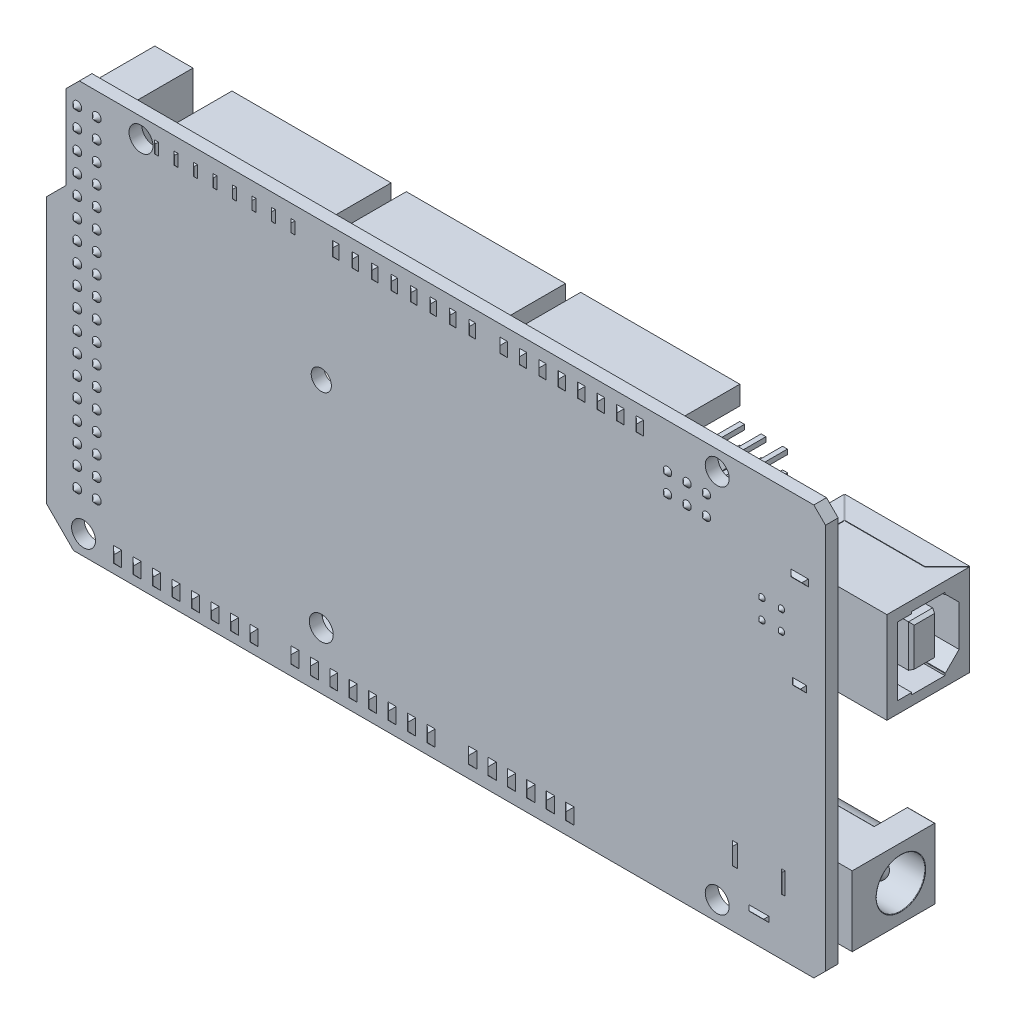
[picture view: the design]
SolidWorks part; units mm, degrees
ref_plane "Front Plane" through (0, 0, 0) normal (0, 0, 1) x (1, 0, 0)
ref_plane "Top Plane" through (0, 0, 0) normal (0, 1, 0) x (1, 0, 0)
ref_plane "Right Plane" through (0, 0, 0) normal (1, 0, 0) x (0, 0, -1)
sketch "Sketch1" plane through (0, 0, 0) normal (0, 0, 1) x (1, 0, 0)
  line L1 (-50.8, 26.7081) -> (50.8, 26.7081)
  line L2 (-50.8, 26.7081) -> (-50.8, -26.7081)
  line L3 (-50.8, -26.7081) -> (50.8, -26.7081)
  line L4 (50.8, 26.7081) -> (50.8, -26.7081)
  line L5 (-50.8, 26.7081) -> (50.8, -26.7081) construction
  line L6 (-50.8, -26.7081) -> (50.8, 26.7081) construction
  point P0 (0, 0)
  dimension "D1" = 101.6
  dimension "D2" = 53.4162
extrude "Boss-Extrude1" add sketch "Sketch1" along normal blind 1.651
sketch "Sketch2" plane through (0, 0, 0) normal (0, 0, -1) x (-1, 0, 0)
  line L0 (50.8, -26.7081) -> (-50.8, -26.7081) construction
  line L1 (41.7576, 25.4889) -> (46.736, 25.4889)
  line L2 (41.7576, 25.4889) -> (41.7576, -20.7899)
  line L3 (41.7576, -20.7899) -> (46.736, -20.7899)
  line L4 (46.736, 25.4889) -> (46.736, -20.7899)
  line L5 (41.7576, 25.4889) -> (46.736, -20.7899) construction
  line L6 (41.7576, -20.7899) -> (46.736, 25.4889) construction
  line L7 (50.8, 26.7081) -> (50.8, -26.7081) construction
  line L8 (-50.8, 26.7081) -> (50.8, 26.7081) construction
  line L9 (36.6776, 25.4381) -> (15.9258, 25.4381)
  line L10 (36.6776, 25.4381) -> (36.6776, 22.9743)
  line L11 (36.6776, 22.9743) -> (15.9258, 22.9743)
  line L12 (15.9258, 25.4381) -> (15.9258, 22.9743)
  line L13 (36.6776, 25.4381) -> (15.9258, 22.9743) construction
  line L14 (36.6776, 22.9743) -> (15.9258, 25.4381) construction
  line L15 (-6.8072, 25.4381) -> (-6.8072, 22.9743)
  line L16 (13.9446, 25.4381) -> (-6.8072, 25.4381)
  line L17 (13.9446, 22.9743) -> (-6.8072, 22.9743)
  line L18 (13.9446, 25.4381) -> (13.9446, 22.9743)
  line L19 (-29.5402, 25.4381) -> (-29.5402, 22.9743)
  line L20 (-8.7884, 25.4381) -> (-29.5402, 25.4381)
  line L21 (-8.7884, 22.9743) -> (-29.5402, 22.9743)
  line L22 (-8.7884, 25.4381) -> (-8.7884, 22.9743)
  line L23 (15.9258, 25.4381) -> (-6.8072, 25.4381) construction
  line L24 (-1.016, -22.8981) -> (-1.016, -25.3619)
  line L25 (42.545, -22.8981) -> (21.717, -22.8981)
  line L26 (42.545, -22.8981) -> (42.545, -25.3619)
  line L27 (42.545, -25.3619) -> (21.717, -25.3619)
  line L28 (21.717, -22.8981) -> (21.717, -25.3619)
  line L29 (42.545, -22.8981) -> (21.717, -25.3619) construction
  line L30 (42.545, -25.3619) -> (21.717, -22.8981) construction
  line L31 (19.812, -22.8981) -> (19.812, -25.3619)
  line L32 (19.812, -22.8981) -> (-1.016, -22.8981)
  line L33 (19.812, -25.3619) -> (-1.016, -25.3619)
  line L35 (-3.175, -22.9125) -> (-18.8722, -22.9125)
  line L36 (-3.175, -22.9125) -> (-3.175, -25.3619)
  line L37 (-3.175, -25.3619) -> (-18.8722, -25.3619)
  line L38 (-18.8722, -22.9125) -> (-18.8722, -25.3619)
  point P0 (44.2468, 2.3495)
  point P9 (26.3017, 24.2062)
  point P16 (32.131, -24.13)
  dimension "D1" = 4.9784
  dimension "D2" = 46.2788
  dimension "D3" = 5.9182
  dimension "D4" = 4.064
  dimension "D5" = 20.7518
  dimension "D6" = 2.4638
  dimension "D7" = 1.27
  dimension "D8" = 5.08
  dimension "D10" = 22.733
  dimension "D11" = 2.4638
  dimension "D12" = 20.828
  dimension "D13" = 8.255
  dimension "D14" = 1.3462
  dimension "D15" = 15.6972
  dimension "D16" = 2
  dimension "D17" = 2.159
  dimension "D18" = 13.7922
  dimension "D9" = 3
extrude "Boss-Extrude2" add sketch "Sketch2" along normal blind 8.5598
sketch "Sketch3" plane through (0, 0, 0) normal (0, 0, -1) x (-1, 0, 0)
  line L0 (-50.8, -26.7081) -> (-50.8, 26.7081) construction
  line L1 (-57.15, 17.4371) -> (-40.8432, 17.4371)
  line L2 (-57.15, 17.4371) -> (-57.15, 5.4991)
  line L3 (-57.15, 5.4991) -> (-40.8432, 5.4991)
  line L4 (-40.8432, 17.4371) -> (-40.8432, 5.4991)
  line L5 (-57.15, 17.4371) -> (-40.8432, 5.4991) construction
  line L6 (-57.15, 5.4991) -> (-40.8432, 17.4371) construction
  line L7 (-50.8, 26.7081) -> (50.8, 26.7081) construction
  point P0 (-48.9966, 11.4681)
  dimension "D1" = 16.3068
  dimension "D2" = 11.938
  dimension "D3" = 6.35
  dimension "D4" = 9.271
extrude "Boss-Extrude3" add sketch "Sketch3" along normal blind 10.795
sketch "Sketch4" plane through (0, 0, 0) normal (0, 0, -1) x (-1, 0, 0)
  line L0 (-50.8, -26.7081) -> (-50.8, 5.4991) construction
  line L1 (-52.6288, -13.7541) -> (-38.4048, -13.7541)
  line L2 (-52.6288, -13.7541) -> (-52.6288, -22.8981)
  line L3 (-52.6288, -22.8981) -> (-38.4048, -22.8981)
  line L4 (-38.4048, -13.7541) -> (-38.4048, -22.8981)
  line L5 (-52.6288, -13.7541) -> (-38.4048, -22.8981) construction
  line L6 (-52.6288, -22.8981) -> (-38.4048, -13.7541) construction
  line L7 (50.8, -26.7081) -> (-50.8, -26.7081) construction
  point P0 (-45.5168, -18.3261)
  dimension "D1" = 9.144
  dimension "D2" = 14.224
  dimension "D3" = 1.8288
  dimension "D4" = 3.81
extrude "Boss-Extrude4" add sketch "Sketch4" along normal blind 6.477
sketch "Sketch5" plane through (0, 0, -6.477) normal (0, 0, -1) x (-1, 0, 0)
  line L0 (-52.6288, -22.8981) -> (-38.4048, -22.8981) construction
  line L1 (-52.6288, -13.7541) -> (-49.0728, -13.7541)
  line L2 (-52.6288, -13.7541) -> (-52.6288, -22.8981)
  line L3 (-52.6288, -22.8981) -> (-49.0728, -22.8981)
  line L4 (-49.0728, -13.7541) -> (-49.0728, -22.8981)
  dimension "D1" = 3.556
extrude "Boss-Extrude5" add sketch "Sketch5" along normal blind 4.318
sketch "Sketch6" plane through (49.0728, 0, 0) normal (-1, 0, 0) x (0, 0, 1)
  line L0 (-6.477, -22.8981) -> (-6.477, -13.7541) construction
  line L1 (-6.477, -14.5161) -> (-6.477, -22.1361)
  arc A0 (-6.477, -14.5161) -> (-6.477, -22.1361) centre (-6.477, -18.3261) ccw
  dimension "D1" = 7.62
extrude "Boss-Extrude6" add sketch "Sketch6" along normal up to surface (10.668 mm away)
sketch "Sketch7" plane through (0, 0, -6.477) normal (0, 0, -1) x (-1, 0, 0)
  line L0 (-38.4048, -14.5161) -> (-49.0728, -14.5161) construction
  line L1 (-38.4048, -13.7541) -> (-40.005, -13.7541)
  line L2 (-38.4048, -13.7541) -> (-38.4048, -14.5161)
  line L3 (-38.4048, -14.5161) -> (-40.005, -14.5161)
  line L4 (-40.005, -13.7541) -> (-40.005, -14.5161)
  line L5 (-49.0728, -22.8981) -> (-38.4048, -22.8981) construction
  line L6 (-38.4048, -22.1361) -> (-40.005, -22.1361)
  line L7 (-38.4048, -22.1361) -> (-38.4048, -22.8981)
  line L8 (-38.4048, -22.8981) -> (-40.005, -22.8981)
  line L9 (-40.005, -22.1361) -> (-40.005, -22.8981)
  dimension "D1" = 1.6002
  dimension "D2" = 1.6002
extrude "Cut-Extrude1" cut sketch "Sketch7" against normal up to surface (6.477 mm away)
sketch "Sketch8" plane through (52.6288, 0, 0) normal (1, 0, 0) x (0, 0, -1)
  line L0 (10.795, -18.3261) -> (0, -18.3261) construction
  line L1 (10.795, -13.7541) -> (10.795, -22.8981) construction
  line L2 (0, -13.7541) -> (0, -22.8981) construction
  circle A0 centre (6.35, -18.3261) radius 3.175
  dimension "D1" = 0
  dimension "D2" = 6.35
  dimension "D3" = 4.445
extrude "Cut-Extrude2" cut sketch "Sketch8" against normal blind 12.065
sketch "Sketch9" plane through (40.5638, 0, 0) normal (1, 0, 0) x (0, 0, -1)
  circle A0 centre (6.35, -18.3261) radius 1.016
  dimension "D1" = 2.032
extrude "Boss-Extrude7" add sketch "Sketch9" along normal blind 10.16
fillet "Fillet1" radius 1.016 1 edges at (50.7238, -17.3101, -6.35)
sketch "Sketch10" plane through (57.15, 0, 0) normal (1, 0, 0) x (0, 0, -1)
  line L0 (10.795, 17.4371) -> (0, 5.4991) construction
  line L1 (10.795, 5.4991) -> (0, 17.4371) construction
  line L2 (10.795, 5.4991) -> (0, 5.4991) construction
  line L3 (7.6389, 15.9131) -> (7.5565, 15.9131)
  line L4 (9.4169, 14.1351) -> (9.4169, 8.8011)
  line L5 (7.6389, 7.0231) -> (7.5565, 7.0231)
  line L6 (1.3781, 15.9131) -> (1.3781, 7.0231)
  line L7 (9.4169, 15.9131) -> (1.3781, 7.0231) construction
  line L8 (9.4169, 7.0231) -> (1.3781, 15.9131) construction
  line L9 (9.4169, 11.4681) -> (1.3781, 11.4681) construction
  line L10 (3.2385, 7.0231) -> (1.3781, 7.0231)
  line L11 (7.5565, 7.0231) -> (7.5565, 6.7691)
  line L12 (7.5565, 6.7691) -> (3.2385, 6.7691)
  line L13 (3.2385, 7.0231) -> (3.2385, 6.7691)
  line L14 (7.5565, 7.2771) -> (3.2385, 6.7691) construction
  line L15 (7.5565, 6.7691) -> (3.2385, 7.2771) construction
  line L16 (3.2385, 15.9131) -> (3.2385, 16.1671)
  line L17 (7.5565, 16.1671) -> (3.2385, 16.1671)
  line L18 (7.5565, 15.9131) -> (7.5565, 16.1671)
  line L19 (3.2385, 15.9131) -> (1.3781, 15.9131)
  line L20 (9.4169, 8.8011) -> (7.6389, 7.0231)
  line L21 (9.4169, 14.1351) -> (7.6389, 15.9131)
  point P8 (5.3975, 11.4681)
  point P15 (5.3975, 7.0231)
  dimension "D1" = 1.524
  dimension "D2" = 0.508
  dimension "D3" = 4.318
  dimension "D4" = 1.778
  dimension "D5" = 1.778
  dimension "D6" = 45
  dimension "D7" = 45
extrude "Cut-Extrude3" cut sketch "Sketch10" against normal blind 13.97
sketch "Sketch11" plane through (43.18, 0, 0) normal (1, 0, 0) x (0, 0, -1)
  line L0 (10.795, 17.4371) -> (0, 5.4991) construction
  line L1 (10.795, 5.4991) -> (0, 17.4371) construction
  line L3 (6.9723, 14.2113) -> (3.8227, 14.2113)
  line L4 (6.9723, 14.2113) -> (6.9723, 8.7249)
  line L5 (6.9723, 8.7249) -> (3.8227, 8.7249)
  line L6 (3.8227, 14.2113) -> (3.8227, 8.7249)
  line L7 (6.9723, 14.2113) -> (3.8227, 8.7249) construction
  line L8 (6.9723, 8.7249) -> (3.8227, 14.2113) construction
  point P8 (5.3975, 11.4681)
  dimension "D1" = 3.1496
  dimension "D2" = 5.4864
extrude "Boss-Extrude8" add sketch "Sketch11" along normal blind 13.462
chamfer "Chamfer1" distance 0.254 angle 63 4 edges at (56.642, 14.2113, -5.3975) (56.642, 11.4681, -6.9723) (56.642, 8.7249, -5.3975) (56.642, 11.4681, -3.8227)
ref_plane "Plane1" through (0, 11.4681, 0) normal (0, 1, 0) x (-1, 0, 0)
sketch "Sketch12" plane through (0, 17.4371, 0) normal (0, 1, 0) x (1, 0, 0)
  line L1 (43.7896, 10.795) -> (57.15, 10.795)
  line L2 (40.8432, 10.7315) -> (43.7896, 7.7851)
  line L3 (43.8531, 7.8486) -> (54.2036, 7.8486)
  line L4 (40.8432, 0) -> (43.7896, 0)
  line L5 (40.9067, 10.795) -> (43.8531, 7.8486)
  line L6 (57.15, 10.795) -> (54.2036, 7.8486)
  line L7 (40.8432, 0) -> (40.8432, 10.7315)
  line L8 (40.9067, 10.795) -> (43.7896, 10.795)
  line L9 (43.7896, 0) -> (43.7896, 7.7851)
  dimension "D1" = 2.9464
  dimension "D2" = 45
  dimension "D3" = 2.9464
  dimension "D4" = 45
  dimension "D5" = 0.0635
  dimension "D6" = 45
extrude "Boss-Extrude9" add sketch "Sketch12" along normal blind 0.0635
mirror "Mirror1" about plane through (0, 11.4681, 0) normal (0, 1, 0) of "Boss-Extrude9"
chamfer "Chamfer2" distance 1.524 angle 45 2 edges at (50.8, -26.7081, 0.8255) (50.8, 26.7081, 0.8255)
chamfer "Chamfer3" distance 3.556 angle 45 1 edges at (-50.8, -26.7081, 0.8255)
sketch "Sketch13" plane through (0, 0, 0) normal (0, 0, -1) x (-1, 0, 0)
  line L1 (50.8, 26.7081) -> (50.8, -23.1521) construction
  line L2 (-49.276, 26.7081) -> (50.8, 26.7081) construction
  line L3 (48.26, 24.9447) -> (48.26, 14.0081)
  line L4 (50.8, 11.4681) -> (48.26, 14.0081)
  line L5 (48.26, 24.9447) -> (46.4966, 26.7081)
  line L6 (46.4966, 26.7081) -> (50.8, 26.7081)
  line L7 (50.8, 26.7081) -> (50.8, 11.4681)
  dimension "D1" = 15.24
  dimension "D2" = 2.54
  dimension "D3" = 45
extrude "Cut-Extrude4" cut sketch "Sketch13" against normal up to next
sketch "Sketch14" plane through (0, 0, 0) normal (0, 0, -1) x (-1, 0, 0)
  line L1 (-6.9605, 8.5631) -> (7.073, 8.5631)
  line L2 (-6.9605, 8.5631) -> (-6.9605, -5.6349)
  line L3 (-6.9605, -5.6349) -> (7.073, -5.6349)
  line L4 (7.073, 8.5631) -> (7.073, -5.6349)
  line L5 (-24.3309, -1.1659) -> (-21.5659, -1.1659)
  line L6 (-24.3309, -1.1659) -> (-24.3309, -2.574)
  line L7 (-24.3309, -2.574) -> (-21.5659, -2.574)
  line L8 (-21.5659, -1.1659) -> (-21.5659, -2.574)
  line L9 (-33.5092, 10.32) -> (-28.4497, 10.32)
  line L10 (-33.5092, 10.32) -> (-33.5092, 5.3949)
  line L11 (-33.5092, 5.3949) -> (-28.4497, 5.3949)
  line L12 (-28.4497, 10.32) -> (-28.4497, 5.3949)
  line L13 (-43.9403, -6.0414) -> (-40.6713, -6.0414)
  line L14 (-43.9403, -6.0414) -> (-43.9403, -12.5341)
  line L15 (-43.9403, -12.5341) -> (-40.6713, -12.5341)
  line L16 (-40.6713, -6.0414) -> (-40.6713, -12.5341)
  line L17 (-31.173, -23.0456) -> (-27.138, -23.0456)
  line L18 (-31.173, -23.0456) -> (-31.173, -25.4924)
  line L19 (-31.173, -25.4924) -> (-27.138, -25.4924)
  line L20 (-27.138, -23.0456) -> (-27.138, -25.4924)
  line L21 (-33.7999, -4.2562) -> (-30.9794, -4.2562)
  line L22 (-33.7999, -4.2562) -> (-33.7999, -7.1173)
  line L23 (-33.7999, -7.1173) -> (-30.9794, -7.1173)
  line L24 (-30.9794, -4.2562) -> (-30.9794, -7.1173)
  line L25 (-32.8056, -8.9233) -> (-31.8519, -8.9233)
  line L26 (-32.8056, -8.9233) -> (-32.8056, -12.1294)
  line L27 (-32.8056, -12.1294) -> (-31.8519, -12.1294)
  line L28 (-31.8519, -8.9233) -> (-31.8519, -12.1294)
  line L29 (-30.0459, -9.4914) -> (-28.4497, -9.4914)
  line L30 (-30.0459, -9.4914) -> (-30.0459, -10.2219)
  line L31 (-30.0459, -10.2219) -> (-28.4497, -10.2219)
  line L32 (-28.4497, -9.4914) -> (-28.4497, -10.2219)
  line L33 (-36.7827, -8.6595) -> (-35.9914, -8.6595)
  line L34 (-36.7827, -8.6595) -> (-36.7827, -10.2219)
  line L35 (-36.7827, -10.2219) -> (-35.9914, -10.2219)
  line L36 (-35.9914, -8.6595) -> (-35.9914, -10.2219)
  line L37 (-48.1172, 1.9462) -> (-44.9541, 1.9462)
  line L38 (-48.1172, 1.9462) -> (-48.1172, -2.574)
  line L39 (-48.1172, -2.574) -> (-44.9541, -2.574)
  line L40 (-44.9541, 1.9462) -> (-44.9541, -2.574)
  line L41 (-42.3058, 0.1921) -> (-41.1584, 0.1921)
  line L42 (-42.3058, 0.1921) -> (-42.3058, -2.574)
  line L43 (-42.3058, -2.574) -> (-41.1584, -2.574)
  line L44 (-41.1584, 0.1921) -> (-41.1584, -2.574)
  line L45 (-12.8797, -19.5259) -> (-11.332, -19.5259)
  line L46 (-12.8797, -19.5259) -> (-12.8797, -20.252)
  line L47 (-12.8797, -20.252) -> (-11.332, -20.252)
  line L48 (-11.332, -19.5259) -> (-11.332, -20.252)
  line L49 (-17.7394, -11.1441) -> (-16.7743, -11.1441)
  line L50 (-17.7394, -11.1441) -> (-17.7394, -13.2747)
  line L51 (-17.7394, -13.2747) -> (-16.7743, -13.2747)
  line L52 (-16.7743, -11.1441) -> (-16.7743, -13.2747)
  line L53 (-10.7102, -11.6175) -> (-9.7086, -11.6175)
  line L54 (-10.7102, -11.6175) -> (-10.7102, -13.0744)
  line L55 (-10.7102, -13.0744) -> (-9.7086, -13.0744)
  line L56 (-9.7086, -11.6175) -> (-9.7086, -13.0744)
  line L57 (-13.0047, -10.7617) -> (-11.73, -10.7617)
  line L58 (-13.0047, -10.7617) -> (-13.0047, -14.0213)
  line L59 (-13.0047, -14.0213) -> (-11.73, -14.0213)
  line L60 (-11.73, -10.7617) -> (-11.73, -14.0213)
  line L61 (-16.091, -10.7617) -> (-14.2392, -10.7617)
  line L62 (-16.091, -10.7617) -> (-16.091, -14.0213)
  line L63 (-16.091, -14.0213) -> (-14.2392, -14.0213)
  line L64 (-14.2392, -10.7617) -> (-14.2392, -14.0213)
  line L65 (-23.6628, -8.3755) -> (-22.1074, -8.3755)
  line L66 (-23.6628, -8.3755) -> (-23.6628, -9.1237)
  line L67 (-23.6628, -9.1237) -> (-22.1074, -9.1237)
  line L68 (-22.1074, -8.3755) -> (-22.1074, -9.1237)
  line L69 (-23.5707, -5.0699) -> (-22.0069, -5.0699)
  line L70 (-23.5707, -5.0699) -> (-23.5707, -5.8311)
  line L71 (-23.5707, -5.8311) -> (-22.0069, -5.8311)
  line L72 (-22.0069, -5.0699) -> (-22.0069, -5.8311)
  line L73 (-39.6477, 4.309) -> (-38.0454, 4.309)
  line L74 (-39.6477, 4.309) -> (-39.6477, 3.6337)
  line L75 (-39.6477, 3.6337) -> (-38.0454, 3.6337)
  line L76 (-38.0454, 4.309) -> (-38.0454, 3.6337)
  line L77 (-39.5152, 2.6802) -> (-38.0454, 2.6802)
  line L78 (-39.5152, 2.6802) -> (-39.5152, 1.9462)
  line L79 (-39.5152, 1.9462) -> (-38.0454, 1.9462)
  line L80 (-38.0454, 2.6802) -> (-38.0454, 1.9462)
  line L81 (-36.3871, 2.6802) -> (-34.854, 2.6802)
  line L82 (-36.3871, 2.6802) -> (-36.3871, 1.9462)
  line L83 (-36.3871, 1.9462) -> (-34.854, 1.9462)
  line L84 (-34.854, 2.6802) -> (-34.854, 1.9462)
  line L85 (-33.1723, 2.8127) -> (-31.5965, 2.8127)
  line L86 (-33.1723, 2.8127) -> (-33.1723, 1.9462)
  line L87 (-33.1723, 1.9462) -> (-31.5965, 1.9462)
  line L88 (-31.5965, 2.8127) -> (-31.5965, 1.9462)
  line L89 (-30.0459, 2.8127) -> (-28.5657, 2.8127)
  line L90 (-30.0459, 2.8127) -> (-30.0459, 1.9462)
  line L91 (-30.0459, 1.9462) -> (-28.5657, 1.9462)
  line L92 (-28.5657, 2.8127) -> (-28.5657, 1.9462)
  line L93 (-26.941, 2.8127) -> (-25.3776, 2.8127)
  line L94 (-26.941, 2.8127) -> (-26.941, 1.9462)
  line L95 (-26.941, 1.9462) -> (-25.3776, 1.9462)
  line L96 (-25.3776, 2.8127) -> (-25.3776, 1.9462)
  line L97 (-23.3697, 5.7605) -> (-22.3121, 5.7605)
  line L98 (-23.3697, 5.7605) -> (-23.3697, 2.5417)
  line L99 (-23.3697, 2.5417) -> (-22.3121, 2.5417)
  line L100 (-22.3121, 5.7605) -> (-22.3121, 2.5417)
  line L101 (-23.8854, 8.0069) -> (-22.1074, 8.0069)
  line L102 (-23.8854, 8.0069) -> (-23.8854, 6.7341)
  line L103 (-23.8854, 6.7341) -> (-22.1074, 6.7341)
  line L104 (-22.1074, 8.0069) -> (-22.1074, 6.7341)
  line L105 (-23.8854, 10.32) -> (-22.1074, 10.32)
  line L106 (-23.8854, 10.32) -> (-23.8854, 9.0606)
  line L107 (-23.8854, 9.0606) -> (-22.1074, 9.0606)
  line L108 (-22.1074, 10.32) -> (-22.1074, 9.0606)
  line L109 (-23.3697, 14.0967) -> (-22.5161, 14.0967)
  line L110 (-23.3697, 14.0967) -> (-23.3697, 10.8407)
  line L111 (-23.3697, 10.8407) -> (-22.5161, 10.8407)
  line L112 (-22.5161, 14.0967) -> (-22.5161, 10.8407)
  line L113 (-23.8854, 15.886) -> (-22.1074, 15.886)
  line L114 (-23.8854, 15.886) -> (-23.8854, 14.654)
  line L115 (-23.8854, 14.654) -> (-22.1074, 14.654)
  line L116 (-22.1074, 15.886) -> (-22.1074, 14.654)
  line L117 (-23.7484, 17.9417) -> (-22.3121, 17.9417)
  line L118 (-23.7484, 17.9417) -> (-23.7484, 17.187)
  line L119 (-23.7484, 17.187) -> (-22.3121, 17.187)
  line L120 (-22.3121, 17.9417) -> (-22.3121, 17.187)
  line L121 (-43.674, 18.8311) -> (-41.7321, 18.8311)
  line L122 (-43.674, 18.8311) -> (-43.674, 17.7416)
  line L123 (-43.674, 17.7416) -> (-41.7321, 17.7416)
  line L124 (-41.7321, 18.8311) -> (-41.7321, 17.7416)
  line L125 (-39.6477, 15.6816) -> (-38.0454, 15.6816)
  line L126 (-39.6477, 15.6816) -> (-39.6477, 14.9091)
  line L127 (-39.6477, 14.9091) -> (-38.0454, 14.9091)
  line L128 (-38.0454, 15.6816) -> (-38.0454, 14.9091)
  line L129 (-39.6477, 13.3641) -> (-38.0454, 13.3641)
  line L130 (-39.6477, 13.3641) -> (-39.6477, 12.4687)
  line L131 (-39.6477, 12.4687) -> (-38.0454, 12.4687)
  line L132 (-38.0454, 13.3641) -> (-38.0454, 12.4687)
  line L133 (-39.3497, 11.7365) -> (-38.3867, 11.7365)
  line L134 (-39.3497, 11.7365) -> (-39.3497, 8.5631)
  line L135 (-39.3497, 8.5631) -> (-38.3867, 8.5631)
  line L136 (-38.3867, 11.7365) -> (-38.3867, 8.5631)
  line L137 (-39.6477, 7.8575) -> (-38.0454, 7.8575)
  line L138 (-39.6477, 7.8575) -> (-39.6477, 6.9215)
  line L139 (-39.6477, 6.9215) -> (-38.0454, 6.9215)
  line L140 (-38.0454, 7.8575) -> (-38.0454, 6.9215)
  line L141 (24.8756, 10.8407) -> (26.6802, 10.8407)
  line L142 (24.8756, 10.8407) -> (24.8756, 9.4206)
  line L143 (24.8756, 9.4206) -> (26.6802, 9.4206)
  line L144 (26.6802, 10.8407) -> (26.6802, 9.4206)
  line L145 (29.6259, 11.7365) -> (30.8732, 11.7365)
  line L146 (29.6259, 11.7365) -> (29.6259, 8.3325)
  line L147 (29.6259, 8.3325) -> (30.8732, 8.3325)
  line L148 (30.8732, 11.7365) -> (30.8732, 8.3325)
  line L149 (-38.9776, 20.9935) -> (-37.1574, 20.9935)
  line L150 (-38.9776, 20.9935) -> (-38.9776, 17.7416)
  line L151 (-38.9776, 17.7416) -> (-37.1574, 17.7416)
  line L152 (-37.1574, 20.9935) -> (-37.1574, 17.7416)
extrude "Boss-Extrude10" add sketch "Sketch14" along normal blind 1.397
sketch "Sketch15" plane through (0, 0, 0) normal (0, 0, -1) x (-1, 0, 0)
  line L1 (20.5142, 4.069) -> (26.9751, 4.069)
  line L2 (20.5142, 4.069) -> (20.5142, -2.21)
  line L3 (20.5142, -2.21) -> (26.9751, -2.21)
  line L4 (26.9751, 4.069) -> (26.9751, -2.21)
extrude "Boss-Extrude11" add sketch "Sketch15" along normal blind 2.286
sketch "Sketch16" plane through (0, 0, -2.286) normal (0, 0, -1) x (-1, 0, 0)
  line L0 (20.5142, 4.069) -> (26.9751, -2.21) construction
  circle A0 centre (23.7447, 0.9295) radius 1.524
  dimension "D1" = 3.048
extrude "Boss-Extrude12" add sketch "Sketch16" along normal blind 1.016
sketch "Sketch17" plane through (0, 0, 0) normal (0, 0, -1) x (-1, 0, 0)
  line L0 (-32.3335, 0.8451) -> (-32.3335, -2.9138) construction
  line L1 (-36.2828, -2.9138) -> (-28.3841, -2.9138)
  line L2 (-36.2828, -2.9138) -> (-36.2828, 0.8451) construction
  line L3 (-36.2828, 0.8451) -> (-28.3841, 0.8451)
  line L4 (-28.3841, -2.9138) -> (-28.3841, 0.8451) construction
  arc A0 (-36.2828, -2.9138) -> (-36.2828, 0.8451) centre (-35.9606, -1.0343) cw
  arc A1 (-28.3841, -2.9138) -> (-28.3841, 0.8451) centre (-28.7063, -1.0343) ccw
extrude "Boss-Extrude13" add sketch "Sketch17" along normal blind 3.3528
fillet "Fillet2" radius 0.508 4 edges at (32.3335, 0.8451, -3.3528) (26.7995, -1.0343, -3.3528) (32.3335, -2.9138, -3.3528) (37.8675, -1.0343, -3.3528)
sketch "Sketch19" plane through (0, 0, 0) normal (0, 0, -1) x (-1, 0, 0)
  circle A0 centre (-32.7701, -18.1074) radius 3.302
  circle A1 centre (-25.5812, -18.1074) radius 3.302
  dimension "D1" = 6.604
extrude "Boss-Extrude14" add sketch "Sketch19" along normal blind 5.461
fillet "Fillet3" radius 0.254 2 edges at (22.2792, -18.1074, -5.461) (29.4681, -18.1074, -5.461)
sketch "Sketch20" plane through (0, 0, 0) normal (0, 0, -1) x (-1, 0, 0)
  line L0 (11.7084, 3.2926) -> (12.7244, 2.2766)
  line L1 (16.103, 4.9732) -> (17.119, 3.9572)
  line L2 (11.7084, 3.9572) -> (11.7084, 3.2926)
  line L3 (12.7244, 2.2766) -> (16.103, 2.2766)
  line L4 (17.119, 3.9572) -> (17.119, 3.2926)
  line L5 (16.103, 2.2766) -> (17.119, 3.2926)
  line L6 (12.7244, 4.9732) -> (16.103, 4.9732)
  line L7 (12.7244, 2.1792) -> (16.103, 2.1792)
  line L8 (12.7244, -0.5174) -> (16.103, -0.5174)
  line L9 (11.7084, 3.9572) -> (12.7244, 4.9732)
  line L10 (11.7084, 0.4986) -> (12.7244, -0.5174)
  line L11 (11.7084, 1.1632) -> (11.7084, 0.4986)
  line L12 (11.7084, 1.1632) -> (12.7244, 2.1792)
  line L13 (16.103, 2.1792) -> (17.119, 1.1632)
  line L14 (17.119, 1.1632) -> (17.119, 0.4986)
  line L15 (16.103, -0.5174) -> (17.119, 0.4986)
  line L16 (12.7244, -0.6148) -> (16.103, -0.6148)
  line L17 (-36.5713, 21.0509) -> (-35.5553, 22.0669)
  line L18 (-35.5553, 22.0669) -> (-34.8949, 22.0669)
  line L19 (-36.5713, 21.0509) -> (-36.5713, 17.6727)
  line L20 (-35.5553, 16.6567) -> (-34.8949, 16.6567)
  line L21 (-33.8789, 21.0509) -> (-33.8789, 17.6727)
  line L22 (12.7244, -3.3114) -> (16.103, -3.3114)
  line L23 (11.7084, -2.2954) -> (12.7244, -3.3114)
  line L24 (11.7084, -1.6308) -> (11.7084, -2.2954)
  line L25 (11.7084, -1.6308) -> (12.7244, -0.6148)
  line L26 (16.103, -0.6148) -> (17.119, -1.6308)
  line L27 (17.119, -1.6308) -> (17.119, -2.2954)
  line L28 (16.103, -3.3114) -> (17.119, -2.2954)
  line L29 (12.7244, 4.9732) -> (12.7244, 2.1792) construction
  line L30 (-34.8949, 22.0669) -> (-33.8789, 21.0509)
  line L31 (-34.8949, 16.6567) -> (-33.8789, 17.6727)
  line L32 (-36.5713, 17.6727) -> (-35.5553, 16.6567)
  line L33 (-32.7613, 22.0669) -> (-32.1009, 22.0669)
  line L34 (-32.1009, 22.0669) -> (-31.0849, 21.0509)
  line L35 (-31.0849, 21.0509) -> (-31.0849, 17.6727)
  line L36 (-32.1009, 16.6567) -> (-31.0849, 17.6727)
  line L37 (-32.7613, 16.6567) -> (-32.1009, 16.6567)
  line L38 (-33.7773, 17.6727) -> (-32.7613, 16.6567)
  line L39 (-33.7773, 21.0509) -> (-33.7773, 17.6727)
  line L40 (-33.7773, 21.0509) -> (-32.7613, 22.0669)
  line L41 (-29.9673, 22.0669) -> (-29.3069, 22.0669)
  line L42 (-29.3069, 22.0669) -> (-28.2909, 21.0509)
  line L43 (-28.2909, 21.0509) -> (-28.2909, 17.6727)
  line L44 (-29.3069, 16.6567) -> (-28.2909, 17.6727)
  line L45 (-29.9673, 16.6567) -> (-29.3069, 16.6567)
  line L46 (-30.9833, 17.6727) -> (-29.9673, 16.6567)
  line L47 (-30.9833, 21.0509) -> (-30.9833, 17.6727)
  line L48 (-30.9833, 21.0509) -> (-29.9673, 22.0669)
  line L49 (-35.5553, 22.0669) -> (-32.7613, 22.0669) construction
  point P0 (11.7084, 4.9732)
  point P1 (17.119, -2.9495)
  point P2 (11.7084, -2.9495)
  point P3 (17.119, 4.9732)
  point P5 (17.119, 2.2766)
  point P6 (11.7084, 2.2766)
  point P14 (-36.5713, 22.0669)
  point P33 (-33.8789, 16.6567)
  point P34 (-36.5713, 16.6567)
  point P35 (-33.8789, 22.0669)
  dimension "D1" = 3
  dimension "D2" = 2.794
  dimension "D3" = 2.6965
  dimension "D8" = 41.029
  dimension "D4" = 5.4102
  dimension "D5" = 2.6924
  dimension "D6" = 5.4106
  dimension "D7" = 2.794
extrude "Boss-Extrude15" add sketch "Sketch20" along normal blind 2.54
sketch "Sketch21" plane through (0, 0, -2.54) normal (0, 0, -1) x (-1, 0, 0)
  line L0 (11.7084, 3.6249) -> (17.119, 3.6249) construction
  line L1 (11.7084, 3.9572) -> (11.7084, 3.2926) construction
  line L2 (17.119, 3.2926) -> (17.119, 3.9572) construction
  line L3 (14.4137, 4.9732) -> (14.4137, -3.3114) construction
  line L4 (16.103, 4.9732) -> (12.7244, 4.9732) construction
  line L5 (12.7244, -3.3114) -> (16.103, -3.3114) construction
  line L6 (12.7627, 1.1484) -> (13.3977, 1.1484)
  line L7 (12.7627, 3.9424) -> (13.3977, 3.9424)
  line L8 (12.7627, 3.9424) -> (12.7627, 3.3074)
  line L9 (12.7627, 3.3074) -> (13.3977, 3.3074)
  line L10 (13.3977, 3.9424) -> (13.3977, 3.3074)
  line L11 (12.7627, 3.9424) -> (13.3977, 3.3074) construction
  line L12 (12.7627, 3.3074) -> (13.3977, 3.9424) construction
  line L13 (12.7627, 1.1484) -> (12.7627, 0.5134)
  line L14 (13.3977, 1.1484) -> (13.3977, 0.5134)
  line L15 (12.7627, 0.5134) -> (13.3977, 0.5134)
  line L16 (12.7627, -1.6456) -> (13.3977, -1.6456)
  line L17 (12.7627, -1.6456) -> (12.7627, -2.2806)
  line L18 (13.3977, -1.6456) -> (13.3977, -2.2806)
  line L19 (12.7627, -2.2806) -> (13.3977, -2.2806)
  line L20 (12.7627, 3.9424) -> (12.7627, 1.1484) construction
  line L21 (15.4297, -1.6456) -> (15.4297, -2.2806)
  line L22 (16.0647, -2.2806) -> (15.4297, -2.2806)
  line L23 (16.0647, -1.6456) -> (16.0647, -2.2806)
  line L24 (16.0647, -1.6456) -> (15.4297, -1.6456)
  line L25 (16.0647, 0.5134) -> (15.4297, 0.5134)
  line L26 (15.4297, 1.1484) -> (15.4297, 0.5134)
  line L27 (16.0647, 1.1484) -> (16.0647, 0.5134)
  line L28 (16.0647, 1.1484) -> (15.4297, 1.1484)
  line L29 (16.0647, 3.3074) -> (15.4297, 3.3074)
  line L30 (15.4297, 3.9424) -> (15.4297, 3.3074)
  line L31 (16.0647, 3.9424) -> (16.0647, 3.3074)
  line L32 (16.0647, 3.9424) -> (15.4297, 3.9424)
  line L33 (-36.5713, 19.3618) -> (-28.2909, 19.3618) construction
  line L34 (-36.5713, 21.0509) -> (-36.5713, 17.6727) construction
  line L35 (-28.2909, 17.6727) -> (-28.2909, 21.0509) construction
  line L36 (-35.2251, 22.0669) -> (-35.2251, 16.6567) construction
  line L37 (-34.8949, 22.0669) -> (-35.5553, 22.0669) construction
  line L38 (-35.5553, 16.6567) -> (-34.8949, 16.6567) construction
  line L39 (-32.7486, 18.3458) -> (-32.7486, 17.7108)
  line L40 (-35.5426, 18.3458) -> (-34.9076, 18.3458)
  line L41 (-35.5426, 18.3458) -> (-35.5426, 17.7108)
  line L42 (-35.5426, 17.7108) -> (-34.9076, 17.7108)
  line L43 (-34.9076, 18.3458) -> (-34.9076, 17.7108)
  line L44 (-35.5426, 18.3458) -> (-34.9076, 17.7108) construction
  line L45 (-35.5426, 17.7108) -> (-34.9076, 18.3458) construction
  line L46 (-32.7486, 18.3458) -> (-32.1136, 18.3458)
  line L47 (-32.1136, 18.3458) -> (-32.1136, 17.7108)
  line L48 (-32.7486, 17.7108) -> (-32.1136, 17.7108)
  line L49 (-29.9546, 18.3458) -> (-29.9546, 17.7108)
  line L50 (-29.9546, 18.3458) -> (-29.3196, 18.3458)
  line L51 (-29.3196, 18.3458) -> (-29.3196, 17.7108)
  line L52 (-29.9546, 17.7108) -> (-29.3196, 17.7108)
  line L53 (-35.5426, 18.3458) -> (-32.7486, 18.3458) construction
  line L54 (-29.9546, 21.0128) -> (-29.3196, 21.0128)
  line L55 (-29.3196, 20.3778) -> (-29.3196, 21.0128)
  line L56 (-29.9546, 20.3778) -> (-29.9546, 21.0128)
  line L57 (-29.9546, 20.3778) -> (-29.3196, 20.3778)
  line L58 (-32.7486, 21.0128) -> (-32.1136, 21.0128)
  line L59 (-32.1136, 20.3778) -> (-32.1136, 21.0128)
  line L60 (-32.7486, 20.3778) -> (-32.7486, 21.0128)
  line L61 (-32.7486, 20.3778) -> (-32.1136, 20.3778)
  line L62 (-35.5426, 21.0128) -> (-34.9076, 21.0128)
  line L63 (-34.9076, 20.3778) -> (-34.9076, 21.0128)
  line L64 (-35.5426, 20.3778) -> (-34.9076, 20.3778)
  line L65 (-35.5426, 20.3778) -> (-35.5426, 21.0128)
  point P12 (13.0802, 3.6249)
  point P51 (-35.2251, 18.0283)
  dimension "D1" = 0.635
  dimension "D2" = 0.635
  dimension "D4" = 2.794
  dimension "D5" = 1.016
  dimension "D6" = 1.016
  dimension "D7" = 0.635
  dimension "D8" = 0.635
  dimension "D9" = 2.794
  dimension "D3" = 3
  dimension "D10" = 3
extrude "Boss-Extrude16" add sketch "Sketch21" along normal blind 6.223
chamfer "Chamfer4" distance 0.127 angle 45 48 edges at (-12.7627, -1.9631, -8.763) (-13.0802, -1.6456, -8.763) (-13.3977, -1.9631, -8.763) (-13.0802, -2.2806, -8.763) (-12.7627, 0.8309, -8.763) (-13.0802, 1.1484, -8.763) (-13.3977, 0.8309, -8.763) (-13.0802, 0.5134, -8.763) (-13.0802, 3.3074, -8.763) (-12.7627, 3.6249, -8.763) (-13.0802, 3.9424, -8.763) (-13.3977, 3.6249, -8.763) (-15.7472, 3.3074, -8.763) (-15.4297, 3.6249, -8.763) (-15.7472, 3.9424, -8.763) (-16.0647, 3.6249, -8.763) (-15.7472, 0.5134, -8.763) (-15.4297, 0.8309, -8.763) (-15.7472, 1.1484, -8.763) (-16.0647, 0.8309, -8.763) (-16.0647, -1.9631, -8.763) (-15.7472, -2.2806, -8.763) (-15.4297, -1.9631, -8.763) (-15.7472, -1.6456, -8.763) (35.2251, 17.7108, -8.763) (35.5426, 18.0283, -8.763) (35.2251, 18.3458, -8.763) (34.9076, 18.0283, -8.763) (35.2251, 21.0128, -8.763) (34.9076, 20.6953, -8.763) (35.2251, 20.3778, -8.763) (35.5426, 20.6953, -8.763) (32.4311, 21.0128, -8.763) (32.1136, 20.6953, -8.763) (32.4311, 20.3778, -8.763) (32.7486, 20.6953, -8.763) (29.6371, 21.0128, -8.763) (29.3196, 20.6953, -8.763) (29.6371, 20.3778, -8.763) (29.9546, 20.6953, -8.763) (32.7486, 18.0283, -8.763) (32.4311, 18.3458, -8.763) (32.1136, 18.0283, -8.763) (32.4311, 17.7108, -8.763) (29.9546, 18.0283, -8.763) (29.6371, 18.3458, -8.763) (29.3196, 18.0283, -8.763) (29.6371, 17.7108, -8.763)
sketch "Sketch22" plane through (0, 0, 0) normal (0, 0, -1) x (-1, 0, 0)
  line L0 (-50.8, -25.1841) -> (-50.8, -22.8981) construction
  line L1 (47.244, -26.7081) -> (-49.276, -26.7081) construction
  line L2 (-36.6776, -24.1681) -> (-36.6776, 25.7302) construction
  line L3 (-49.276, 26.7081) -> (46.4966, 26.7081) construction
  line L4 (14.9479, -19.2896) -> (14.9479, 8.7266) construction
  line L5 (50.8, 11.4681) -> (50.8, -23.1521) construction
  circle A0 centre (38.4556, 24.1681) radius 1.5621
  circle A1 centre (14.9479, 8.7266) radius 1.3153
  circle A2 centre (14.9479, -19.2896) radius 1.5621
  circle A3 centre (45.9486, -24.1681) radius 1.5621
  circle A4 centre (-36.6776, -24.1681) radius 1.5621
  circle A5 centre (-36.6776, 24.1681) radius 1.5621
  dimension "D1" = 3.1242
  dimension "D2" = 14.1224
  dimension "D3" = 2.54
  dimension "D4" = 2.54
  dimension "D5" = 82.6262
  dimension "D6" = 2.54
  dimension "D7" = 2.54
  dimension "D8" = 75.1332
  dimension "D9" = 28.0162
  dimension "D10" = 0
  dimension "D11" = 0
  dimension "D12" = 0
  dimension "D13" = 35.8521
extrude "Cut-Extrude5" cut sketch "Sketch22" against normal up to next
sketch "Sketch24" plane through (0, 0, -8.5598) normal (0, 0, -1) x (-1, 0, 0)
  line L0 (44.2468, 25.4889) -> (44.2468, -20.7899) construction
  line L1 (46.736, 25.4889) -> (41.7576, 25.4889) construction
  line L2 (41.7576, -20.7899) -> (46.736, -20.7899) construction
  line L3 (44.2468, 25.4889) -> (46.736, 25.4889) construction
  line L4 (41.7576, 2.3495) -> (46.736, 2.3495) construction
  line L5 (41.7576, 25.4889) -> (41.7576, -20.7899) construction
  line L6 (46.736, -20.7899) -> (46.736, 25.4889) construction
  line L7 (45.4914, 25.4889) -> (45.4914, 2.3495) construction
  line L8 (42.6402, 24.1681) -> (42.6402, 23.4442)
  line L9 (43.3641, 23.4442) -> (42.6402, 23.4442)
  line L10 (45.1294, 24.1681) -> (45.8533, 24.1681)
  line L11 (45.1294, 24.1681) -> (45.1294, 23.4442)
  line L12 (45.1294, 23.4442) -> (45.8533, 23.4442)
  line L13 (45.8533, 24.1681) -> (45.8533, 23.4442)
  line L14 (45.1294, 24.1681) -> (45.8533, 23.4442) construction
  line L15 (45.1294, 23.4442) -> (45.8533, 24.1681) construction
  line L16 (43.3641, 24.1681) -> (42.6402, 24.1681)
  line L17 (43.3641, 24.1681) -> (43.3641, 23.4442)
  line L18 (43.3642, 21.6281) -> (42.6403, 21.6281)
  line L19 (42.6403, 21.6281) -> (42.6403, 20.9042)
  line L20 (43.3642, 20.9042) -> (42.6403, 20.9042)
  line L21 (43.3642, 21.6281) -> (43.3642, 20.9042)
  line L22 (45.1295, 21.6281) -> (45.8534, 21.6281)
  line L23 (45.1295, 21.6281) -> (45.1295, 20.9042)
  line L24 (45.1295, 20.9042) -> (45.8534, 20.9042)
  line L25 (45.8534, 21.6281) -> (45.8534, 20.9042)
  line L26 (43.3642, 19.0881) -> (42.6403, 19.0881)
  line L27 (42.6403, 19.0881) -> (42.6403, 18.3642)
  line L28 (43.3642, 18.3642) -> (42.6403, 18.3642)
  line L29 (43.3642, 19.0881) -> (43.3642, 18.3642)
  line L30 (45.1295, 19.0881) -> (45.8534, 19.0881)
  line L31 (45.1295, 19.0881) -> (45.1295, 18.3642)
  line L32 (45.1295, 18.3642) -> (45.8534, 18.3642)
  line L33 (45.8534, 19.0881) -> (45.8534, 18.3642)
  line L34 (43.3642, 16.5481) -> (42.6403, 16.5481)
  line L35 (42.6403, 16.5481) -> (42.6403, 15.8242)
  line L36 (43.3642, 15.8242) -> (42.6403, 15.8242)
  line L37 (43.3642, 16.5481) -> (43.3642, 15.8242)
  line L38 (45.1295, 16.5481) -> (45.8534, 16.5481)
  line L39 (45.1295, 16.5481) -> (45.1295, 15.8242)
  line L40 (45.1295, 15.8242) -> (45.8534, 15.8242)
  line L41 (45.8534, 16.5481) -> (45.8534, 15.8242)
  line L42 (43.3642, 14.0081) -> (42.6403, 14.0081)
  line L43 (42.6403, 14.0081) -> (42.6403, 13.2842)
  line L44 (43.3642, 13.2842) -> (42.6403, 13.2842)
  line L45 (43.3642, 14.0081) -> (43.3642, 13.2842)
  line L46 (45.1295, 14.0081) -> (45.8534, 14.0081)
  line L47 (45.1295, 14.0081) -> (45.1295, 13.2842)
  line L48 (45.1295, 13.2842) -> (45.8534, 13.2842)
  line L49 (45.8534, 14.0081) -> (45.8534, 13.2842)
  line L50 (43.3642, 11.4681) -> (42.6403, 11.4681)
  line L51 (42.6403, 11.4681) -> (42.6403, 10.7442)
  line L52 (43.3642, 10.7442) -> (42.6403, 10.7442)
  line L53 (43.3642, 11.4681) -> (43.3642, 10.7442)
  line L54 (45.1295, 11.4681) -> (45.8534, 11.4681)
  line L55 (45.1295, 11.4681) -> (45.1295, 10.7442)
  line L56 (45.1295, 10.7442) -> (45.8534, 10.7442)
  line L57 (45.8534, 11.4681) -> (45.8534, 10.7442)
  line L58 (43.3642, 8.9281) -> (42.6403, 8.9281)
  line L59 (42.6403, 8.9281) -> (42.6403, 8.2042)
  line L60 (43.3642, 8.2042) -> (42.6403, 8.2042)
  line L61 (43.3642, 8.9281) -> (43.3642, 8.2042)
  line L62 (45.1295, 8.9281) -> (45.8534, 8.9281)
  line L63 (45.1295, 8.9281) -> (45.1295, 8.2042)
  line L64 (45.1295, 8.2042) -> (45.8534, 8.2042)
  line L65 (45.8534, 8.9281) -> (45.8534, 8.2042)
  line L66 (43.3642, 6.3881) -> (42.6403, 6.3881)
  line L67 (42.6403, 6.3881) -> (42.6403, 5.6642)
  line L68 (43.3642, 5.6642) -> (42.6403, 5.6642)
  line L69 (43.3642, 6.3881) -> (43.3642, 5.6642)
  line L70 (45.1295, 6.3881) -> (45.8534, 6.3881)
  line L71 (45.1295, 6.3881) -> (45.1295, 5.6642)
  line L72 (45.1295, 5.6642) -> (45.8534, 5.6642)
  line L73 (45.8534, 6.3881) -> (45.8534, 5.6642)
  line L74 (43.3642, 3.8481) -> (42.6403, 3.8481)
  line L75 (42.6403, 3.8481) -> (42.6403, 3.1242)
  line L76 (43.3642, 3.1242) -> (42.6403, 3.1242)
  line L77 (43.3642, 3.8481) -> (43.3642, 3.1242)
  line L78 (45.1295, 3.8481) -> (45.8534, 3.8481)
  line L79 (45.1295, 3.8481) -> (45.1295, 3.1242)
  line L80 (45.1295, 3.1242) -> (45.8534, 3.1242)
  line L81 (45.8534, 3.8481) -> (45.8534, 3.1242)
  line L82 (43.3642, 1.3081) -> (42.6403, 1.3081)
  line L83 (42.6403, 1.3081) -> (42.6403, 0.5842)
  line L84 (43.3642, 0.5842) -> (42.6403, 0.5842)
  line L85 (43.3642, 1.3081) -> (43.3642, 0.5842)
  line L86 (45.1295, 1.3081) -> (45.8534, 1.3081)
  line L87 (45.1295, 1.3081) -> (45.1295, 0.5842)
  line L88 (45.1295, 0.5842) -> (45.8534, 0.5842)
  line L89 (45.8534, 1.3081) -> (45.8534, 0.5842)
  line L90 (43.3642, -1.2319) -> (42.6403, -1.2319)
  line L91 (42.6403, -1.2319) -> (42.6403, -1.9558)
  line L92 (43.3642, -1.9558) -> (42.6403, -1.9558)
  line L93 (43.3642, -1.2319) -> (43.3642, -1.9558)
  line L94 (45.1295, -1.2319) -> (45.8534, -1.2319)
  line L95 (45.1295, -1.2319) -> (45.1295, -1.9558)
  line L96 (45.1295, -1.9558) -> (45.8534, -1.9558)
  line L97 (45.8534, -1.2319) -> (45.8534, -1.9558)
  line L98 (43.3642, -3.7719) -> (42.6403, -3.7719)
  line L99 (42.6403, -3.7719) -> (42.6403, -4.4958)
  line L100 (43.3642, -4.4958) -> (42.6403, -4.4958)
  line L101 (43.3642, -3.7719) -> (43.3642, -4.4958)
  line L102 (45.1295, -3.7719) -> (45.8534, -3.7719)
  line L103 (45.1295, -3.7719) -> (45.1295, -4.4958)
  line L104 (45.1295, -4.4958) -> (45.8534, -4.4958)
  line L105 (45.8534, -3.7719) -> (45.8534, -4.4958)
  line L106 (43.3642, -6.3119) -> (42.6403, -6.3119)
  line L107 (42.6403, -6.3119) -> (42.6403, -7.0358)
  line L108 (43.3642, -7.0358) -> (42.6403, -7.0358)
  line L109 (43.3642, -6.3119) -> (43.3642, -7.0358)
  line L110 (45.1295, -6.3119) -> (45.8534, -6.3119)
  line L111 (45.1295, -6.3119) -> (45.1295, -7.0358)
  line L112 (45.1295, -7.0358) -> (45.8534, -7.0358)
  line L113 (45.8534, -6.3119) -> (45.8534, -7.0358)
  line L114 (43.3642, -8.8519) -> (42.6403, -8.8519)
  line L115 (42.6403, -8.8519) -> (42.6403, -9.5758)
  line L116 (43.3642, -9.5758) -> (42.6403, -9.5758)
  line L117 (43.3642, -8.8519) -> (43.3642, -9.5758)
  line L118 (45.1295, -8.8519) -> (45.8534, -8.8519)
  line L119 (45.1295, -8.8519) -> (45.1295, -9.5758)
  line L120 (45.1295, -9.5758) -> (45.8534, -9.5758)
  line L121 (45.8534, -8.8519) -> (45.8534, -9.5758)
  line L122 (43.3642, -11.3919) -> (42.6403, -11.3919)
  line L123 (42.6403, -11.3919) -> (42.6403, -12.1158)
  line L124 (43.3642, -12.1158) -> (42.6403, -12.1158)
  line L125 (43.3642, -11.3919) -> (43.3642, -12.1158)
  line L126 (45.1295, -11.3919) -> (45.8534, -11.3919)
  line L127 (45.1295, -11.3919) -> (45.1295, -12.1158)
  line L128 (45.1295, -12.1158) -> (45.8534, -12.1158)
  line L129 (45.8534, -11.3919) -> (45.8534, -12.1158)
  line L130 (43.3642, -13.9319) -> (42.6403, -13.9319)
  line L131 (42.6403, -13.9319) -> (42.6403, -14.6558)
  line L132 (43.3642, -14.6558) -> (42.6403, -14.6558)
  line L133 (43.3642, -13.9319) -> (43.3642, -14.6558)
  line L134 (45.1295, -13.9319) -> (45.8534, -13.9319)
  line L135 (45.1295, -13.9319) -> (45.1295, -14.6558)
  line L136 (45.1295, -14.6558) -> (45.8534, -14.6558)
  line L137 (45.8534, -13.9319) -> (45.8534, -14.6558)
  line L138 (43.3642, -16.4719) -> (42.6403, -16.4719)
  line L139 (42.6403, -16.4719) -> (42.6403, -17.1958)
  line L140 (43.3642, -17.1958) -> (42.6403, -17.1958)
  line L141 (43.3642, -16.4719) -> (43.3642, -17.1958)
  line L142 (45.1295, -16.4719) -> (45.8534, -16.4719)
  line L143 (45.1295, -16.4719) -> (45.1295, -17.1958)
  line L144 (45.1295, -17.1958) -> (45.8534, -17.1958)
  line L145 (45.8534, -16.4719) -> (45.8534, -17.1958)
  line L146 (43.3642, -19.0119) -> (42.6403, -19.0119)
  line L147 (42.6403, -19.0119) -> (42.6403, -19.7358)
  line L148 (43.3642, -19.7358) -> (42.6403, -19.7358)
  line L149 (43.3642, -19.0119) -> (43.3642, -19.7358)
  line L150 (45.1295, -19.0119) -> (45.8534, -19.0119)
  line L151 (45.1295, -19.0119) -> (45.1295, -19.7358)
  line L152 (45.1295, -19.7358) -> (45.8534, -19.7358)
  line L153 (45.8534, -19.0119) -> (45.8534, -19.7358)
  line L154 (15.9258, 24.2062) -> (36.6776, 24.2062) construction
  line L155 (15.9258, 25.4381) -> (15.9258, 22.9743) construction
  line L156 (36.6776, 22.9743) -> (36.6776, 25.4381) construction
  line L157 (32.0929, 24.5682) -> (32.0929, 23.8443)
  line L158 (34.6329, 24.5682) -> (35.3568, 24.5682)
  line L159 (34.6329, 24.5682) -> (34.6329, 23.8443)
  line L160 (34.6329, 23.8443) -> (35.3568, 23.8443)
  line L161 (35.3568, 24.5682) -> (35.3568, 23.8443)
  line L162 (34.6329, 24.5682) -> (35.3568, 23.8443) construction
  line L163 (34.6329, 23.8443) -> (35.3568, 24.5682) construction
  line L164 (32.8168, 24.5682) -> (32.8168, 23.8443)
  line L165 (32.0929, 24.5682) -> (32.8168, 24.5682)
  line L166 (32.0929, 23.8443) -> (32.8168, 23.8443)
  line L167 (29.5529, 24.5682) -> (29.5529, 23.8443)
  line L168 (30.2768, 24.5682) -> (30.2768, 23.8443)
  line L169 (29.5529, 24.5682) -> (30.2768, 24.5682)
  line L170 (29.5529, 23.8443) -> (30.2768, 23.8443)
  line L171 (27.0129, 24.5682) -> (27.0129, 23.8443)
  line L172 (27.7368, 24.5682) -> (27.7368, 23.8443)
  line L173 (27.0129, 24.5682) -> (27.7368, 24.5682)
  line L174 (27.0129, 23.8443) -> (27.7368, 23.8443)
  line L175 (24.4729, 24.5682) -> (24.4729, 23.8443)
  line L176 (25.1968, 24.5682) -> (25.1968, 23.8443)
  line L177 (24.4729, 24.5682) -> (25.1968, 24.5682)
  line L178 (24.4729, 23.8443) -> (25.1968, 23.8443)
  line L179 (21.9329, 24.5681) -> (21.9329, 23.8442)
  line L180 (22.6568, 24.5681) -> (22.6568, 23.8442)
  line L181 (21.9329, 24.5681) -> (22.6568, 24.5681)
  line L182 (21.9329, 23.8442) -> (22.6568, 23.8442)
  line L183 (19.3929, 24.5681) -> (19.3929, 23.8442)
  line L184 (20.1168, 24.5681) -> (20.1168, 23.8442)
  line L185 (19.3929, 24.5681) -> (20.1168, 24.5681)
  line L186 (19.3929, 23.8442) -> (20.1168, 23.8442)
  line L187 (16.8529, 24.5681) -> (16.8529, 23.8442)
  line L188 (17.5768, 24.5681) -> (17.5768, 23.8442)
  line L189 (16.8529, 24.5681) -> (17.5768, 24.5681)
  line L190 (16.8529, 23.8442) -> (17.5768, 23.8442)
  line L191 (13.9446, 24.2062) -> (-6.8072, 24.2062) construction
  line L192 (13.9446, 22.9743) -> (13.9446, 25.4381) construction
  line L193 (-6.8072, 25.4381) -> (-6.8072, 22.9743) construction
  line L194 (9.3599, 24.5681) -> (10.0838, 24.5681)
  line L195 (11.8999, 24.5681) -> (12.6238, 24.5681)
  line L196 (11.8999, 24.5681) -> (11.8999, 23.8442)
  line L197 (11.8999, 23.8442) -> (12.6238, 23.8442)
  line L198 (12.6238, 24.5681) -> (12.6238, 23.8442)
  line L199 (11.8999, 24.5681) -> (12.6238, 23.8442) construction
  line L200 (11.8999, 23.8442) -> (12.6238, 24.5681) construction
  line L201 (9.3599, 24.5681) -> (9.3599, 23.8442)
  line L202 (9.3599, 23.8442) -> (10.0838, 23.8442)
  line L203 (10.0838, 24.5681) -> (10.0838, 23.8442)
  line L204 (6.8199, 24.5681) -> (7.5438, 24.5681)
  line L205 (6.8199, 24.5681) -> (6.8199, 23.8442)
  line L206 (6.8199, 23.8442) -> (7.5438, 23.8442)
  line L207 (7.5438, 24.5681) -> (7.5438, 23.8442)
  line L208 (4.2799, 24.5681) -> (5.0038, 24.5681)
  line L209 (4.2799, 24.5681) -> (4.2799, 23.8442)
  line L210 (4.2799, 23.8442) -> (5.0038, 23.8442)
  line L211 (5.0038, 24.5681) -> (5.0038, 23.8442)
  line L212 (1.7399, 24.5681) -> (2.4638, 24.5681)
  line L213 (1.7399, 24.5681) -> (1.7399, 23.8442)
  line L214 (1.7399, 23.8442) -> (2.4638, 23.8442)
  line L215 (2.4638, 24.5681) -> (2.4638, 23.8442)
  line L216 (-0.8001, 24.5681) -> (-0.0762, 24.5681)
  line L217 (-0.8001, 24.5681) -> (-0.8001, 23.8442)
  line L218 (-0.8001, 23.8442) -> (-0.0762, 23.8442)
  line L219 (-0.0762, 24.5681) -> (-0.0762, 23.8442)
  line L220 (-3.3401, 24.5681) -> (-2.6162, 24.5681)
  line L221 (-3.3401, 24.5681) -> (-3.3401, 23.8442)
  line L222 (-3.3401, 23.8442) -> (-2.6162, 23.8442)
  line L223 (-2.6162, 24.5681) -> (-2.6162, 23.8442)
  line L224 (-5.8801, 24.5681) -> (-5.1562, 24.5681)
  line L225 (-5.8801, 24.5681) -> (-5.8801, 23.8442)
  line L226 (-5.8801, 23.8442) -> (-5.1562, 23.8442)
  line L227 (-5.1562, 24.5681) -> (-5.1562, 23.8442)
  line L228 (-29.5402, 24.2062) -> (-8.7884, 24.2062) construction
  line L229 (-29.5402, 25.4381) -> (-29.5402, 22.9743) construction
  line L230 (-8.7884, 22.9743) -> (-8.7884, 25.4381) construction
  line L231 (-13.3731, 24.5681) -> (-12.6492, 24.5681)
  line L232 (-10.8331, 24.5681) -> (-10.1092, 24.5681)
  line L233 (-10.8331, 24.5681) -> (-10.8331, 23.8442)
  line L234 (-10.8331, 23.8442) -> (-10.1092, 23.8442)
  line L235 (-10.1092, 24.5681) -> (-10.1092, 23.8442)
  line L236 (-10.8331, 24.5681) -> (-10.1092, 23.8442) construction
  line L237 (-10.8331, 23.8442) -> (-10.1092, 24.5681) construction
  line L238 (-12.6492, 24.5681) -> (-12.6492, 23.8442)
  line L239 (-13.3731, 23.8442) -> (-12.6492, 23.8442)
  line L240 (-13.3731, 24.5681) -> (-13.3731, 23.8442)
  line L241 (-15.9131, 24.5681) -> (-15.1892, 24.5681)
  line L242 (-15.1892, 24.5681) -> (-15.1892, 23.8442)
  line L243 (-15.9131, 23.8442) -> (-15.1892, 23.8442)
  line L244 (-15.9131, 24.5681) -> (-15.9131, 23.8442)
  line L245 (-18.4531, 24.5681) -> (-17.7292, 24.5681)
  line L246 (-17.7292, 24.5681) -> (-17.7292, 23.8442)
  line L247 (-18.4531, 23.8442) -> (-17.7292, 23.8442)
  line L248 (-18.4531, 24.5681) -> (-18.4531, 23.8442)
  line L249 (-20.9931, 24.5681) -> (-20.2692, 24.5681)
  line L250 (-20.2692, 24.5681) -> (-20.2692, 23.8442)
  line L251 (-20.9931, 23.8442) -> (-20.2692, 23.8442)
  line L252 (-20.9931, 24.5681) -> (-20.9931, 23.8442)
  line L253 (-23.5331, 24.5681) -> (-22.8092, 24.5681)
  line L254 (-22.8092, 24.5681) -> (-22.8092, 23.8442)
  line L255 (-23.5331, 23.8442) -> (-22.8092, 23.8442)
  line L256 (-23.5331, 24.5681) -> (-23.5331, 23.8442)
  line L257 (-26.0731, 24.5681) -> (-25.3492, 24.5681)
  line L258 (-25.3492, 24.5681) -> (-25.3492, 23.8442)
  line L259 (-26.0731, 23.8442) -> (-25.3492, 23.8442)
  line L260 (-26.0731, 24.5681) -> (-26.0731, 23.8442)
  line L261 (-28.6131, 24.5681) -> (-27.8892, 24.5681)
  line L262 (-27.8892, 24.5681) -> (-27.8892, 23.8442)
  line L263 (-28.6131, 23.8442) -> (-27.8892, 23.8442)
  line L264 (-28.6131, 24.5681) -> (-28.6131, 23.8442)
  line L265 (42.545, -24.13) -> (21.717, -24.13) construction
  line L266 (42.545, -25.3619) -> (42.545, -22.8981) construction
  line L267 (21.717, -22.8981) -> (21.717, -25.3619) construction
  line L268 (42.545, -25.3619) -> (42.545, -22.8981) construction
  line L269 (40.5003, -23.7681) -> (41.2242, -23.7681)
  line L270 (40.5003, -23.7681) -> (40.5003, -24.492)
  line L271 (40.5003, -24.492) -> (41.2242, -24.492)
  line L272 (41.2242, -23.7681) -> (41.2242, -24.492)
  line L273 (40.5003, -23.7681) -> (41.2242, -24.492) construction
  line L274 (40.5003, -24.492) -> (41.2242, -23.7681) construction
  line L275 (37.9603, -23.7681) -> (38.6842, -23.7681)
  line L276 (37.9603, -23.7681) -> (37.9603, -24.492)
  line L277 (38.6842, -23.7681) -> (38.6842, -24.492)
  line L278 (37.9603, -24.492) -> (38.6842, -24.492)
  line L279 (35.4203, -23.7681) -> (36.1442, -23.7681)
  line L280 (35.4203, -23.7681) -> (35.4203, -24.492)
  line L281 (36.1442, -23.7681) -> (36.1442, -24.492)
  line L282 (35.4203, -24.492) -> (36.1442, -24.492)
  line L283 (32.8803, -23.7681) -> (33.6042, -23.7681)
  line L284 (32.8803, -23.7681) -> (32.8803, -24.492)
  line L285 (33.6042, -23.7681) -> (33.6042, -24.492)
  line L286 (32.8803, -24.492) -> (33.6042, -24.492)
  line L287 (30.3403, -23.7681) -> (31.0642, -23.7681)
  line L288 (30.3403, -23.7681) -> (30.3403, -24.492)
  line L289 (31.0642, -23.7681) -> (31.0642, -24.492)
  line L290 (30.3403, -24.492) -> (31.0642, -24.492)
  line L291 (27.8003, -23.7681) -> (28.5242, -23.7681)
  line L292 (27.8003, -23.7681) -> (27.8003, -24.492)
  line L293 (28.5242, -23.7681) -> (28.5242, -24.492)
  line L294 (27.8003, -24.492) -> (28.5242, -24.492)
  line L295 (25.2603, -23.7681) -> (25.9842, -23.7681)
  line L296 (25.2603, -23.7681) -> (25.2603, -24.492)
  line L297 (25.9842, -23.7681) -> (25.9842, -24.492)
  line L298 (25.2603, -24.492) -> (25.9842, -24.492)
  line L299 (22.7203, -23.7681) -> (23.4442, -23.7681)
  line L300 (22.7203, -23.7681) -> (22.7203, -24.492)
  line L301 (23.4442, -23.7681) -> (23.4442, -24.492)
  line L302 (22.7203, -24.492) -> (23.4442, -24.492)
  line L303 (-1.016, -24.13) -> (19.812, -24.13) construction
  line L304 (-1.016, -22.8981) -> (-1.016, -25.3619) construction
  line L305 (19.812, -25.3619) -> (19.812, -22.8981) construction
  line L306 (15.2273, -23.7681) -> (15.9512, -23.7681)
  line L307 (17.7673, -23.7681) -> (18.4912, -23.7681)
  line L308 (17.7673, -23.7681) -> (17.7673, -24.492)
  line L309 (17.7673, -24.492) -> (18.4912, -24.492)
  line L310 (18.4912, -23.7681) -> (18.4912, -24.492)
  line L311 (17.7673, -23.7681) -> (18.4912, -24.492) construction
  line L312 (17.7673, -24.492) -> (18.4912, -23.7681) construction
  line L313 (15.2273, -23.7681) -> (15.2273, -24.492)
  line L314 (15.9512, -23.7681) -> (15.9512, -24.492)
  line L315 (15.2273, -24.492) -> (15.9512, -24.492)
  line L316 (12.6873, -23.7681) -> (13.4112, -23.7681)
  line L317 (12.6873, -23.7681) -> (12.6873, -24.492)
  line L318 (13.4112, -23.7681) -> (13.4112, -24.492)
  line L319 (12.6873, -24.492) -> (13.4112, -24.492)
  line L320 (10.1473, -23.7681) -> (10.8712, -23.7681)
  line L321 (10.1473, -23.7681) -> (10.1473, -24.492)
  line L322 (10.8712, -23.7681) -> (10.8712, -24.492)
  line L323 (10.1473, -24.492) -> (10.8712, -24.492)
  line L324 (7.6073, -23.7681) -> (8.3312, -23.7681)
  line L325 (7.6073, -23.7681) -> (7.6073, -24.492)
  line L326 (8.3312, -23.7681) -> (8.3312, -24.492)
  line L327 (7.6073, -24.492) -> (8.3312, -24.492)
  line L328 (5.0673, -23.7681) -> (5.7912, -23.7681)
  line L329 (5.0673, -23.7681) -> (5.0673, -24.492)
  line L330 (5.7912, -23.7681) -> (5.7912, -24.492)
  line L331 (5.0673, -24.492) -> (5.7912, -24.492)
  line L332 (2.5273, -23.7681) -> (3.2512, -23.7681)
  line L333 (2.5273, -23.7681) -> (2.5273, -24.492)
  line L334 (3.2512, -23.7681) -> (3.2512, -24.492)
  line L335 (2.5273, -24.492) -> (3.2512, -24.492)
  line L336 (-0.0127, -23.7681) -> (0.7112, -23.7681)
  line L337 (-0.0127, -23.7681) -> (-0.0127, -24.492)
  line L338 (0.7112, -23.7681) -> (0.7112, -24.492)
  line L339 (-0.0127, -24.492) -> (0.7112, -24.492)
  line L340 (-18.8722, -24.1372) -> (-3.175, -24.1372) construction
  line L341 (-18.8722, -22.9125) -> (-18.8722, -25.3619) construction
  line L342 (-3.175, -25.3619) -> (-3.175, -22.9125) construction
  line L343 (-3.175, -25.3619) -> (-3.175, -22.9125) construction
  line L344 (-5.2197, -23.7752) -> (-4.4958, -23.7752)
  line L345 (-5.2197, -23.7752) -> (-5.2197, -24.4991)
  line L346 (-5.2197, -24.4991) -> (-4.4958, -24.4991)
  line L347 (-4.4958, -23.7752) -> (-4.4958, -24.4991)
  line L348 (-5.2197, -23.7752) -> (-4.4958, -24.4991) construction
  line L349 (-5.2197, -24.4991) -> (-4.4958, -23.7752) construction
  line L350 (-7.0358, -23.7752) -> (-7.0358, -24.4991)
  line L351 (-7.7597, -23.7752) -> (-7.0358, -23.7752)
  line L352 (-7.7597, -23.7752) -> (-7.7597, -24.4991)
  line L353 (-7.7597, -24.4991) -> (-7.0358, -24.4991)
  line L354 (-9.5758, -23.7752) -> (-9.5758, -24.4991)
  line L355 (-10.2997, -23.7752) -> (-9.5758, -23.7752)
  line L356 (-10.2997, -23.7752) -> (-10.2997, -24.4991)
  line L357 (-10.2997, -24.4991) -> (-9.5758, -24.4991)
  line L358 (-12.1158, -23.7752) -> (-12.1158, -24.4991)
  line L359 (-12.8397, -23.7752) -> (-12.1158, -23.7752)
  line L360 (-12.8397, -23.7752) -> (-12.8397, -24.4991)
  line L361 (-12.8397, -24.4991) -> (-12.1158, -24.4991)
  line L362 (-14.6558, -23.7752) -> (-14.6558, -24.4991)
  line L363 (-15.3797, -23.7752) -> (-14.6558, -23.7752)
  line L364 (-15.3797, -23.7752) -> (-15.3797, -24.4991)
  line L365 (-15.3797, -24.4991) -> (-14.6558, -24.4991)
  line L366 (-17.1958, -23.7752) -> (-17.1958, -24.4991)
  line L367 (-17.9197, -23.7752) -> (-17.1958, -23.7752)
  line L368 (-17.9197, -23.7752) -> (-17.9197, -24.4991)
  line L369 (-17.9197, -24.4991) -> (-17.1958, -24.4991)
  point P17 (45.4914, 23.8061)
  point P167 (34.9948, 24.2062)
  point P206 (12.2618, 24.2062)
  point P245 (-10.4712, 24.2062)
  point P284 (40.8623, -24.13)
  point P325 (18.1292, -24.13)
  point P364 (-4.8577, -24.1372)
  dimension "D1" = 0.7239
  dimension "D2" = 0.7239
  dimension "D3" = 1.3208
  dimension "D5" = 0.7239
  dimension "D6" = 0.7239
  dimension "D7" = 1.3208
  dimension "D8" = 0.7239
  dimension "D9" = 0.7239
  dimension "D10" = 1.3208
  dimension "D11" = 0.7239
  dimension "D12" = 1.3208
  dimension "D13" = 0.7239
  dimension "D14" = 0.7239
  dimension "D15" = 1.3208
  dimension "D16" = 0.7239
  dimension "D17" = 1.3208
  dimension "D18" = 0.7239
  dimension "D19" = 0.7239
  dimension "D20" = 1.3208
  dimension "D4" = 18
extrude "Cut-Extrude6" cut sketch "Sketch24" against normal blind 6.35
chamfer "Chamfer5" distance 0.127 angle 45 356 edges at (-26.3017, 25.4381, -8.5598) (-36.6776, 24.2062, -8.5598) (-26.3017, 22.9743, -8.5598) (-15.9258, 24.2062, -8.5598) (-34.6329, 24.2062, -8.5598) (-34.9948, 23.8443, -8.5598) (-35.3568, 24.2062, -8.5598) (-34.9948, 24.5682, -8.5598) (-32.4548, 24.5682, -8.5598) (-32.0929, 24.2062, -8.5598) (-32.4548, 23.8443, -8.5598) (-32.8168, 24.2062, -8.5598) (-29.9148, 24.5682, -8.5598) (-29.5529, 24.2062, -8.5598) (-29.9148, 23.8443, -8.5598) (-30.2768, 24.2062, -8.5598) (-27.3748, 24.5682, -8.5598) (-27.0129, 24.2062, -8.5598) (-27.3748, 23.8443, -8.5598) (-27.7368, 24.2062, -8.5598) (-24.8348, 24.5682, -8.5598) (-24.4729, 24.2062, -8.5598) (-24.8348, 23.8443, -8.5598) (-25.1968, 24.2062, -8.5598) (-22.2948, 24.5681, -8.5598) (-21.9329, 24.2062, -8.5598) (-22.2948, 23.8442, -8.5598) (-22.6568, 24.2062, -8.5598) (-19.7548, 24.5681, -8.5598) (-19.3929, 24.2062, -8.5598) (-19.7548, 23.8442, -8.5598) (-20.1168, 24.2062, -8.5598) (-17.2148, 24.5681, -8.5598) (-16.8529, 24.2062, -8.5598) (-17.2148, 23.8442, -8.5598) (-17.5768, 24.2062, -8.5598) (6.8072, 24.2062, -8.5598) (-3.5687, 25.4381, -8.5598) (-13.9446, 24.2062, -8.5598) (-3.5687, 22.9743, -8.5598) (-12.2618, 24.5681, -8.5598) (-11.8999, 24.2062, -8.5598) (-12.2618, 23.8442, -8.5598) (-12.6238, 24.2062, -8.5598) (-9.7218, 24.5681, -8.5598) (-9.3599, 24.2062, -8.5598) (-9.7218, 23.8442, -8.5598) (-10.0838, 24.2062, -8.5598) (-7.1818, 24.5681, -8.5598) (-6.8199, 24.2062, -8.5598) (-7.1818, 23.8442, -8.5598) (-7.5438, 24.2062, -8.5598) (-4.6418, 24.5681, -8.5598) (-4.2799, 24.2062, -8.5598) (-4.6418, 23.8442, -8.5598) (-5.0038, 24.2062, -8.5598) (-2.1018, 24.5681, -8.5598) (-1.7399, 24.2062, -8.5598) (-2.1018, 23.8442, -8.5598) (-2.4638, 24.2062, -8.5598) (0.4382, 24.5681, -8.5598) (0.8001, 24.2062, -8.5598) (0.4382, 23.8442, -8.5598) (0.0762, 24.2062, -8.5598) (2.9782, 24.5681, -8.5598) (3.3401, 24.2062, -8.5598) (2.9782, 23.8442, -8.5598) (2.6162, 24.2062, -8.5598) (5.5182, 24.5681, -8.5598) (5.8801, 24.2062, -8.5598) (5.5182, 23.8442, -8.5598) (5.1562, 24.2062, -8.5598) (29.5402, 24.2062, -8.5598) (19.1643, 25.4381, -8.5598) (8.7884, 24.2062, -8.5598) (19.1643, 22.9743, -8.5598) (10.4712, 24.5681, -8.5598) (10.8331, 24.2062, -8.5598) (10.4712, 23.8442, -8.5598) (10.1092, 24.2062, -8.5598) (12.6492, 24.2062, -8.5598) (13.0112, 24.5681, -8.5598) (13.3731, 24.2062, -8.5598) (13.0112, 23.8442, -8.5598) (15.1892, 24.2062, -8.5598) (15.5512, 24.5681, -8.5598) (15.9131, 24.2062, -8.5598) (15.5512, 23.8442, -8.5598) (17.7292, 24.2062, -8.5598) (18.0912, 24.5681, -8.5598) (18.4531, 24.2062, -8.5598) (18.0912, 23.8442, -8.5598) (20.2692, 24.2062, -8.5598) (20.6312, 24.5681, -8.5598) (20.9931, 24.2062, -8.5598) (20.6312, 23.8442, -8.5598) (22.8092, 24.2062, -8.5598) (23.1712, 24.5681, -8.5598) (23.5331, 24.2062, -8.5598) (23.1712, 23.8442, -8.5598) (25.3492, 24.2062, -8.5598) (25.7112, 24.5681, -8.5598) (26.0731, 24.2062, -8.5598) (25.7112, 23.8442, -8.5598) (27.8892, 24.2062, -8.5598) (28.2512, 24.5681, -8.5598) (28.6131, 24.2062, -8.5598) (28.2512, 23.8442, -8.5598) (-44.2468, -20.7899, -8.5598) (-41.7576, 2.3495, -8.5598) (-44.2468, 25.4889, -8.5598) (-46.736, 2.3495, -8.5598) (-42.6402, 23.8061, -8.5598) (-43.0022, 23.4442, -8.5598) (-43.3641, 23.8061, -8.5598) (-43.0022, 24.1681, -8.5598) (-45.4914, 24.1681, -8.5598) (-45.1294, 23.8061, -8.5598) (-45.4914, 23.4442, -8.5598) (-45.8533, 23.8061, -8.5598) (-43.0022, 20.9042, -8.5598) (-43.3642, 21.2661, -8.5598) (-43.0022, 21.6281, -8.5598) (-42.6403, 21.2661, -8.5598) (-45.4914, 21.6281, -8.5598) (-45.1295, 21.2661, -8.5598) (-45.4914, 20.9042, -8.5598) (-45.8534, 21.2661, -8.5598) (-43.0022, 18.3642, -8.5598) (-43.3642, 18.7261, -8.5598) (-43.0022, 19.0881, -8.5598) (-42.6403, 18.7261, -8.5598) (-45.4914, 19.0881, -8.5598) (-45.1295, 18.7261, -8.5598) (-45.4914, 18.3642, -8.5598) (-45.8534, 18.7261, -8.5598) (-43.0022, 15.8242, -8.5598) (-43.3642, 16.1861, -8.5598) (-43.0022, 16.5481, -8.5598) (-42.6403, 16.1861, -8.5598) (-45.4914, 16.5481, -8.5598) (-45.1295, 16.1861, -8.5598) (-45.4914, 15.8242, -8.5598) (-45.8534, 16.1861, -8.5598) (-43.0022, 13.2842, -8.5598) (-43.3642, 13.6461, -8.5598) (-43.0022, 14.0081, -8.5598) (-42.6403, 13.6461, -8.5598) (-45.4914, 14.0081, -8.5598) (-45.1295, 13.6461, -8.5598) (-45.4914, 13.2842, -8.5598) (-45.8534, 13.6461, -8.5598) (-43.0022, 10.7442, -8.5598) (-43.3642, 11.1061, -8.5598) (-43.0022, 11.4681, -8.5598) (-42.6403, 11.1061, -8.5598) (-45.4914, 11.4681, -8.5598) (-45.1295, 11.1061, -8.5598) (-45.4914, 10.7442, -8.5598) (-45.8534, 11.1061, -8.5598) (-43.0022, 8.2042, -8.5598) (-43.3642, 8.5661, -8.5598) (-43.0022, 8.9281, -8.5598) (-42.6403, 8.5661, -8.5598) (-45.4914, 8.9281, -8.5598) (-45.1295, 8.5661, -8.5598) (-45.4914, 8.2042, -8.5598) (-45.8534, 8.5661, -8.5598) (-43.0022, 5.6642, -8.5598) (-43.3642, 6.0261, -8.5598) (-43.0022, 6.3881, -8.5598) (-42.6403, 6.0261, -8.5598) (-45.4914, 6.3881, -8.5598) (-45.1295, 6.0261, -8.5598) (-45.4914, 5.6642, -8.5598) (-45.8534, 6.0261, -8.5598) (-43.0022, 3.1242, -8.5598) (-43.3642, 3.4861, -8.5598) (-43.0022, 3.8481, -8.5598) (-42.6403, 3.4861, -8.5598) (-45.4914, 3.8481, -8.5598) (-45.1295, 3.4861, -8.5598) (-45.4914, 3.1242, -8.5598) (-45.8534, 3.4861, -8.5598) (-43.0022, 0.5842, -8.5598) (-43.3642, 0.9461, -8.5598) (-43.0022, 1.3081, -8.5598) (-42.6403, 0.9461, -8.5598) (-45.4914, 1.3081, -8.5598) (-45.1295, 0.9461, -8.5598) (-45.4914, 0.5842, -8.5598) (-45.8534, 0.9461, -8.5598) (-43.0022, -1.9558, -8.5598) (-43.3642, -1.5939, -8.5598) (-43.0022, -1.2319, -8.5598) (-42.6403, -1.5939, -8.5598) (-45.4914, -1.2319, -8.5598) (-45.1295, -1.5939, -8.5598) (-45.4914, -1.9558, -8.5598) (-45.8534, -1.5939, -8.5598) (-43.0022, -4.4958, -8.5598) (-43.3642, -4.1339, -8.5598) (-43.0022, -3.7719, -8.5598) (-42.6403, -4.1339, -8.5598) (-45.4914, -3.7719, -8.5598) (-45.1295, -4.1339, -8.5598) (-45.4914, -4.4958, -8.5598) (-45.8534, -4.1339, -8.5598) (-43.0022, -7.0358, -8.5598) (-43.3642, -6.6739, -8.5598) (-43.0022, -6.3119, -8.5598) (-42.6403, -6.6739, -8.5598) (-45.4914, -6.3119, -8.5598) (-45.1295, -6.6739, -8.5598) (-45.4914, -7.0358, -8.5598) (-45.8534, -6.6739, -8.5598) (-43.0022, -9.5758, -8.5598) (-43.3642, -9.2139, -8.5598) (-43.0022, -8.8519, -8.5598) (-42.6403, -9.2139, -8.5598) (-45.4914, -8.8519, -8.5598) (-45.1295, -9.2139, -8.5598) (-45.4914, -9.5758, -8.5598) (-45.8534, -9.2139, -8.5598) (-43.0022, -12.1158, -8.5598) (-43.3642, -11.7539, -8.5598) (-43.0022, -11.3919, -8.5598) (-42.6403, -11.7539, -8.5598) (-45.4914, -11.3919, -8.5598) (-45.1295, -11.7539, -8.5598) (-45.4914, -12.1158, -8.5598) (-45.8534, -11.7539, -8.5598) (-43.0022, -14.6558, -8.5598) (-43.3642, -14.2939, -8.5598) (-43.0022, -13.9319, -8.5598) (-42.6403, -14.2939, -8.5598) (-45.4914, -13.9319, -8.5598) (-45.1295, -14.2939, -8.5598) (-45.4914, -14.6558, -8.5598) (-45.8534, -14.2939, -8.5598) (-43.0022, -17.1958, -8.5598) (-43.3642, -16.8339, -8.5598) (-43.0022, -16.4719, -8.5598) (-42.6403, -16.8339, -8.5598) (-45.4914, -16.4719, -8.5598) (-45.1295, -16.8339, -8.5598) (-45.4914, -17.1958, -8.5598) (-45.8534, -16.8339, -8.5598) (-43.0022, -19.7358, -8.5598) (-43.3642, -19.3739, -8.5598) (-43.0022, -19.0119, -8.5598) (-42.6403, -19.3739, -8.5598) (-45.4914, -19.0119, -8.5598) (-45.1295, -19.3739, -8.5598) (-45.4914, -19.7358, -8.5598) (-45.8534, -19.3739, -8.5598) (11.0236, -25.3619, -8.5598) (18.8722, -24.1372, -8.5598) (11.0236, -22.9125, -8.5598) (3.175, -24.1372, -8.5598) (5.2197, -24.1372, -8.5598) (4.8577, -24.4991, -8.5598) (4.4958, -24.1372, -8.5598) (4.8577, -23.7752, -8.5598) (7.3977, -23.7752, -8.5598) (7.7597, -24.1372, -8.5598) (7.3977, -24.4991, -8.5598) (7.0358, -24.1372, -8.5598) (9.9377, -23.7752, -8.5598) (10.2997, -24.1372, -8.5598) (9.9377, -24.4991, -8.5598) (9.5758, -24.1372, -8.5598) (12.4777, -23.7752, -8.5598) (12.8397, -24.1372, -8.5598) (12.4777, -24.4991, -8.5598) (12.1158, -24.1372, -8.5598) (15.0177, -23.7752, -8.5598) (15.3797, -24.1372, -8.5598) (15.0177, -24.4991, -8.5598) (14.6558, -24.1372, -8.5598) (17.5578, -23.7752, -8.5598) (17.9197, -24.1372, -8.5598) (17.5578, -24.4991, -8.5598) (17.1958, -24.1372, -8.5598) (1.016, -24.13, -8.5598) (-9.398, -22.8981, -8.5598) (-19.812, -24.13, -8.5598) (-9.398, -25.3619, -8.5598) (-18.1292, -23.7681, -8.5598) (-17.7673, -24.13, -8.5598) (-18.1292, -24.492, -8.5598) (-18.4912, -24.13, -8.5598) (-15.9512, -24.13, -8.5598) (-15.5892, -23.7681, -8.5598) (-15.2273, -24.13, -8.5598) (-15.5892, -24.492, -8.5598) (-13.4112, -24.13, -8.5598) (-13.0492, -23.7681, -8.5598) (-12.6873, -24.13, -8.5598) (-13.0492, -24.492, -8.5598) (-10.8712, -24.13, -8.5598) (-10.5092, -23.7681, -8.5598) (-10.1473, -24.13, -8.5598) (-10.5092, -24.492, -8.5598) (-8.3312, -24.13, -8.5598) (-7.9692, -23.7681, -8.5598) (-7.6073, -24.13, -8.5598) (-7.9692, -24.492, -8.5598) (-5.7912, -24.13, -8.5598) (-5.4292, -23.7681, -8.5598) (-5.0673, -24.13, -8.5598) (-5.4292, -24.492, -8.5598) (-3.2512, -24.13, -8.5598) (-2.8892, -23.7681, -8.5598) (-2.5273, -24.13, -8.5598) (-2.8892, -24.492, -8.5598) (-0.7112, -24.13, -8.5598) (-0.3492, -23.7681, -8.5598) (0.0127, -24.13, -8.5598) (-0.3492, -24.492, -8.5598) (-32.131, -22.8981, -8.5598) (-42.545, -24.13, -8.5598) (-32.131, -25.3619, -8.5598) (-21.717, -24.13, -8.5598) (-40.5003, -24.13, -8.5598) (-40.8623, -24.492, -8.5598) (-41.2242, -24.13, -8.5598) (-40.8623, -23.7681, -8.5598) (-38.3223, -23.7681, -8.5598) (-37.9603, -24.13, -8.5598) (-38.3223, -24.492, -8.5598) (-38.6842, -24.13, -8.5598) (-35.7823, -23.7681, -8.5598) (-35.4203, -24.13, -8.5598) (-35.7823, -24.492, -8.5598) (-36.1442, -24.13, -8.5598) (-33.2422, -23.7681, -8.5598) (-32.8803, -24.13, -8.5598) (-33.2422, -24.492, -8.5598) (-33.6042, -24.13, -8.5598) (-30.7022, -23.7681, -8.5598) (-30.3403, -24.13, -8.5598) (-30.7022, -24.492, -8.5598) (-31.0642, -24.13, -8.5598) (-28.1623, -23.7681, -8.5598) (-27.8003, -24.13, -8.5598) (-28.1623, -24.492, -8.5598) (-28.5242, -24.13, -8.5598) (-25.6223, -23.7681, -8.5598) (-25.2603, -24.13, -8.5598) (-25.6223, -24.492, -8.5598) (-25.9842, -24.13, -8.5598) (-23.0823, -23.7681, -8.5598) (-22.7203, -24.13, -8.5598) (-23.0823, -24.492, -8.5598) (-23.4442, -24.13, -8.5598)
sketch "Sketch25" plane through (0, 0, 1.651) normal (0, 0, 1) x (1, 0, 0)
  line L0 (-39.5014, -23.5195) -> (-38.4303, -25.533) construction
  line L1 (-42.0414, -23.5195) -> (-40.9703, -23.5195)
  line L2 (-42.0414, -23.5195) -> (-42.0414, -25.533)
  line L3 (-42.0414, -25.533) -> (-40.9703, -25.533)
  line L4 (-40.9703, -23.5195) -> (-40.9703, -25.533)
  line L5 (-42.0414, -23.5195) -> (-40.9703, -25.533) construction
  line L6 (-42.0414, -25.533) -> (-40.9703, -23.5195) construction
  line L7 (-39.5014, -25.533) -> (-38.4303, -23.5195) construction
  line L8 (-39.5014, -23.5195) -> (-39.5014, -25.533)
  line L9 (-39.5014, -23.5195) -> (-38.4303, -23.5195)
  line L10 (-38.4303, -23.5195) -> (-38.4303, -25.533)
  line L11 (-39.5014, -25.533) -> (-38.4303, -25.533)
  line L12 (-36.9614, -23.5195) -> (-35.8903, -25.533) construction
  line L13 (-36.9614, -25.533) -> (-35.8903, -23.5195) construction
  line L14 (-36.9614, -23.5195) -> (-36.9614, -25.533)
  line L15 (-36.9614, -23.5195) -> (-35.8903, -23.5195)
  line L16 (-35.8903, -23.5195) -> (-35.8903, -25.533)
  line L17 (-36.9614, -25.533) -> (-35.8903, -25.533)
  line L18 (-34.4214, -23.5195) -> (-33.3503, -25.533) construction
  line L19 (-34.4214, -25.533) -> (-33.3503, -23.5195) construction
  line L20 (-34.4214, -23.5195) -> (-34.4214, -25.533)
  line L21 (-34.4214, -23.5195) -> (-33.3503, -23.5195)
  line L22 (-33.3503, -23.5195) -> (-33.3503, -25.533)
  line L23 (-34.4214, -25.533) -> (-33.3503, -25.533)
  line L24 (-31.8814, -23.5195) -> (-30.8103, -25.533) construction
  line L25 (-31.8814, -25.533) -> (-30.8103, -23.5195) construction
  line L26 (-31.8814, -23.5195) -> (-31.8814, -25.533)
  line L27 (-31.8814, -23.5195) -> (-30.8103, -23.5195)
  line L28 (-30.8103, -23.5195) -> (-30.8103, -25.533)
  line L29 (-31.8814, -25.533) -> (-30.8103, -25.533)
  line L30 (-29.3414, -23.5195) -> (-28.2703, -25.533) construction
  line L31 (-29.3414, -25.533) -> (-28.2703, -23.5195) construction
  line L32 (-29.3414, -23.5195) -> (-29.3414, -25.533)
  line L33 (-29.3414, -23.5195) -> (-28.2703, -23.5195)
  line L34 (-28.2703, -23.5195) -> (-28.2703, -25.533)
  line L35 (-29.3414, -25.533) -> (-28.2703, -25.533)
  line L36 (-26.8014, -23.5195) -> (-25.7303, -25.533) construction
  line L37 (-26.8014, -25.533) -> (-25.7303, -23.5195) construction
  line L38 (-26.8014, -23.5195) -> (-26.8014, -25.533)
  line L39 (-26.8014, -23.5195) -> (-25.7303, -23.5195)
  line L40 (-25.7303, -23.5195) -> (-25.7303, -25.533)
  line L41 (-26.8014, -25.533) -> (-25.7303, -25.533)
  line L42 (-24.2614, -23.5195) -> (-23.1903, -25.533) construction
  line L43 (-24.2614, -25.533) -> (-23.1903, -23.5195) construction
  line L44 (-24.2614, -23.5195) -> (-24.2614, -25.533)
  line L45 (-24.2614, -23.5195) -> (-23.1903, -23.5195)
  line L46 (-23.1903, -23.5195) -> (-23.1903, -25.533)
  line L47 (-24.2614, -25.533) -> (-23.1903, -25.533)
  line L48 (-16.3844, -23.2784) -> (-15.3425, -25.3621) construction
  line L49 (-18.9244, -23.2784) -> (-17.8825, -23.2784)
  line L50 (-18.9244, -23.2784) -> (-18.9244, -25.3621)
  line L51 (-18.9244, -25.3621) -> (-17.8825, -25.3621)
  line L52 (-17.8825, -23.2784) -> (-17.8825, -25.3621)
  line L53 (-18.9244, -23.2784) -> (-17.8825, -25.3621) construction
  line L54 (-18.9244, -25.3621) -> (-17.8825, -23.2784) construction
  line L55 (-16.3844, -25.3621) -> (-15.3425, -23.2784) construction
  line L56 (-16.3844, -23.2784) -> (-16.3844, -25.3621)
  line L57 (-16.3844, -23.2784) -> (-15.3425, -23.2784)
  line L58 (-15.3425, -23.2784) -> (-15.3425, -25.3621)
  line L59 (-16.3844, -25.3621) -> (-15.3425, -25.3621)
  line L60 (-13.8444, -23.2784) -> (-12.8025, -25.3621) construction
  line L61 (-13.8444, -25.3621) -> (-12.8025, -23.2784) construction
  line L62 (-13.8444, -23.2784) -> (-13.8444, -25.3621)
  line L63 (-13.8444, -23.2784) -> (-12.8025, -23.2784)
  line L64 (-12.8025, -23.2784) -> (-12.8025, -25.3621)
  line L65 (-13.8444, -25.3621) -> (-12.8025, -25.3621)
  line L66 (-11.3044, -23.2784) -> (-10.2625, -25.3621) construction
  line L67 (-11.3044, -25.3621) -> (-10.2625, -23.2784) construction
  line L68 (-11.3044, -23.2784) -> (-11.3044, -25.3621)
  line L69 (-11.3044, -23.2784) -> (-10.2625, -23.2784)
  line L70 (-10.2625, -23.2784) -> (-10.2625, -25.3621)
  line L71 (-11.3044, -25.3621) -> (-10.2625, -25.3621)
  line L72 (-8.7644, -23.2784) -> (-7.7225, -25.3621) construction
  line L73 (-8.7644, -25.3621) -> (-7.7225, -23.2784) construction
  line L74 (-8.7644, -23.2784) -> (-8.7644, -25.3621)
  line L75 (-8.7644, -23.2784) -> (-7.7225, -23.2784)
  line L76 (-7.7225, -23.2784) -> (-7.7225, -25.3621)
  line L77 (-8.7644, -25.3621) -> (-7.7225, -25.3621)
  line L78 (-6.2244, -23.2784) -> (-5.1825, -25.3621) construction
  line L79 (-6.2244, -25.3621) -> (-5.1825, -23.2784) construction
  line L80 (-6.2244, -23.2784) -> (-6.2244, -25.3621)
  line L81 (-6.2244, -23.2784) -> (-5.1825, -23.2784)
  line L82 (-5.1825, -23.2784) -> (-5.1825, -25.3621)
  line L83 (-6.2244, -25.3621) -> (-5.1825, -25.3621)
  line L84 (-3.6844, -23.2784) -> (-2.6425, -25.3621) construction
  line L85 (-3.6844, -25.3621) -> (-2.6425, -23.2784) construction
  line L86 (-3.6844, -23.2784) -> (-3.6844, -25.3621)
  line L87 (-3.6844, -23.2784) -> (-2.6425, -23.2784)
  line L88 (-2.6425, -23.2784) -> (-2.6425, -25.3621)
  line L89 (-3.6844, -25.3621) -> (-2.6425, -25.3621)
  line L90 (-1.1444, -23.2784) -> (-0.1025, -25.3621) construction
  line L91 (-1.1444, -25.3621) -> (-0.1025, -23.2784) construction
  line L92 (-1.1444, -23.2784) -> (-1.1444, -25.3621)
  line L93 (-1.1444, -23.2784) -> (-0.1025, -23.2784)
  line L94 (-0.1025, -23.2784) -> (-0.1025, -25.3621)
  line L95 (-1.1444, -25.3621) -> (-0.1025, -25.3621)
  line L96 (6.7626, -23.0214) -> (7.8663, -25.0963) construction
  line L97 (4.2226, -23.0214) -> (5.3263, -23.0214)
  line L98 (4.2226, -23.0214) -> (4.2226, -25.0963)
  line L99 (4.2226, -25.0963) -> (5.3263, -25.0963)
  line L100 (5.3263, -23.0214) -> (5.3263, -25.0963)
  line L101 (4.2226, -23.0214) -> (5.3263, -25.0963) construction
  line L102 (4.2226, -25.0963) -> (5.3263, -23.0214) construction
  line L103 (6.7626, -25.0963) -> (7.8663, -23.0214) construction
  line L104 (6.7626, -23.0214) -> (6.7626, -25.0963)
  line L105 (6.7626, -23.0214) -> (7.8663, -23.0214)
  line L106 (7.8663, -23.0214) -> (7.8663, -25.0963)
  line L107 (6.7626, -25.0963) -> (7.8663, -25.0963)
  line L108 (9.3026, -23.0214) -> (10.4063, -25.0963) construction
  line L109 (9.3026, -25.0963) -> (10.4063, -23.0214) construction
  line L110 (9.3026, -23.0214) -> (9.3026, -25.0963)
  line L111 (9.3026, -23.0214) -> (10.4063, -23.0214)
  line L112 (10.4063, -23.0214) -> (10.4063, -25.0963)
  line L113 (9.3026, -25.0963) -> (10.4063, -25.0963)
  line L114 (11.8426, -23.0214) -> (12.9463, -25.0963) construction
  line L115 (11.8426, -25.0963) -> (12.9463, -23.0214) construction
  line L116 (11.8426, -23.0214) -> (11.8426, -25.0963)
  line L117 (11.8426, -23.0214) -> (12.9463, -23.0214)
  line L118 (12.9463, -23.0214) -> (12.9463, -25.0963)
  line L119 (11.8426, -25.0963) -> (12.9463, -25.0963)
  line L120 (14.3826, -23.0214) -> (15.4863, -25.0963) construction
  line L121 (14.3826, -25.0963) -> (15.4863, -23.0214) construction
  line L122 (14.3826, -23.0214) -> (14.3826, -25.0963)
  line L123 (14.3826, -23.0214) -> (15.4863, -23.0214)
  line L124 (15.4863, -23.0214) -> (15.4863, -25.0963)
  line L125 (14.3826, -25.0963) -> (15.4863, -25.0963)
  line L126 (16.9226, -23.0214) -> (18.0263, -25.0963) construction
  line L127 (16.9226, -25.0963) -> (18.0263, -23.0214) construction
  line L128 (16.9226, -23.0214) -> (16.9226, -25.0963)
  line L129 (16.9226, -23.0214) -> (18.0263, -23.0214)
  line L130 (18.0263, -23.0214) -> (18.0263, -25.0963)
  line L131 (16.9226, -25.0963) -> (18.0263, -25.0963)
  line L132 (-34.1384, 24.9598) -> (-33.6333, 23.3636) construction
  line L133 (-36.6784, 24.9598) -> (-36.1733, 24.9598)
  line L134 (-36.6784, 24.9598) -> (-36.6784, 23.3636)
  line L135 (-36.6784, 23.3636) -> (-36.1733, 23.3636)
  line L136 (-36.1733, 24.9598) -> (-36.1733, 23.3636)
  line L137 (-36.6784, 24.9598) -> (-36.1733, 23.3636) construction
  line L138 (-36.6784, 23.3636) -> (-36.1733, 24.9598) construction
  line L139 (-34.1384, 23.3636) -> (-33.6333, 24.9598) construction
  line L140 (-34.1384, 24.9598) -> (-34.1384, 23.3636)
  line L141 (-34.1384, 24.9598) -> (-33.6333, 24.9598)
  line L142 (-33.6333, 24.9598) -> (-33.6333, 23.3636)
  line L143 (-34.1384, 23.3636) -> (-33.6333, 23.3636)
  line L144 (-31.5984, 24.9598) -> (-31.0933, 23.3636) construction
  line L145 (-31.5984, 23.3636) -> (-31.0933, 24.9598) construction
  line L146 (-31.5984, 24.9598) -> (-31.5984, 23.3636)
  line L147 (-31.5984, 24.9598) -> (-31.0933, 24.9598)
  line L148 (-31.0933, 24.9598) -> (-31.0933, 23.3636)
  line L149 (-31.5984, 23.3636) -> (-31.0933, 23.3636)
  line L150 (-29.0584, 24.9598) -> (-28.5533, 23.3636) construction
  line L151 (-29.0584, 23.3636) -> (-28.5533, 24.9598) construction
  line L152 (-29.0584, 24.9598) -> (-29.0584, 23.3636)
  line L153 (-29.0584, 24.9598) -> (-28.5533, 24.9598)
  line L154 (-28.5533, 24.9598) -> (-28.5533, 23.3636)
  line L155 (-29.0584, 23.3636) -> (-28.5533, 23.3636)
  line L156 (-26.5184, 24.9598) -> (-26.0133, 23.3636) construction
  line L157 (-26.5184, 23.3636) -> (-26.0133, 24.9598) construction
  line L158 (-26.5184, 24.9598) -> (-26.5184, 23.3636)
  line L159 (-26.5184, 24.9598) -> (-26.0133, 24.9598)
  line L160 (-26.0133, 24.9598) -> (-26.0133, 23.3636)
  line L161 (-26.5184, 23.3636) -> (-26.0133, 23.3636)
  line L162 (-23.9784, 24.9598) -> (-23.4733, 23.3636) construction
  line L163 (-23.9784, 23.3636) -> (-23.4733, 24.9598) construction
  line L164 (-23.9784, 24.9598) -> (-23.9784, 23.3636)
  line L165 (-23.9784, 24.9598) -> (-23.4733, 24.9598)
  line L166 (-23.4733, 24.9598) -> (-23.4733, 23.3636)
  line L167 (-23.9784, 23.3636) -> (-23.4733, 23.3636)
  line L168 (-21.4384, 24.9598) -> (-20.9333, 23.3636) construction
  line L169 (-21.4384, 23.3636) -> (-20.9333, 24.9598) construction
  line L170 (-21.4384, 24.9598) -> (-21.4384, 23.3636)
  line L171 (-21.4384, 24.9598) -> (-20.9333, 24.9598)
  line L172 (-20.9333, 24.9598) -> (-20.9333, 23.3636)
  line L173 (-21.4384, 23.3636) -> (-20.9333, 23.3636)
  line L174 (-18.8984, 24.9598) -> (-18.3933, 23.3636) construction
  line L175 (-18.8984, 23.3636) -> (-18.3933, 24.9598) construction
  line L176 (-18.8984, 24.9598) -> (-18.8984, 23.3636)
  line L177 (-18.8984, 24.9598) -> (-18.3933, 24.9598)
  line L178 (-18.3933, 24.9598) -> (-18.3933, 23.3636)
  line L179 (-18.8984, 23.3636) -> (-18.3933, 23.3636)
  line L180 (-10.9163, 25.2056) -> (-10.0827, 23.3636) construction
  line L181 (-13.4563, 25.2056) -> (-12.6227, 25.2056)
  line L182 (-13.4563, 25.2056) -> (-13.4563, 23.3636)
  line L183 (-13.4563, 23.3636) -> (-12.6227, 23.3636)
  line L184 (-12.6227, 25.2056) -> (-12.6227, 23.3636)
  line L185 (-13.4563, 25.2056) -> (-12.6227, 23.3636) construction
  line L186 (-13.4563, 23.3636) -> (-12.6227, 25.2056) construction
  line L187 (-10.9163, 23.3636) -> (-10.0827, 25.2056) construction
  line L188 (-10.9163, 25.2056) -> (-10.9163, 23.3636)
  line L189 (-10.9163, 25.2056) -> (-10.0827, 25.2056)
  line L190 (-10.0827, 25.2056) -> (-10.0827, 23.3636)
  line L191 (-10.9163, 23.3636) -> (-10.0827, 23.3636)
  line L192 (-8.3763, 25.2056) -> (-7.5427, 23.3636) construction
  line L193 (-8.3763, 23.3636) -> (-7.5427, 25.2056) construction
  line L194 (-8.3763, 25.2056) -> (-8.3763, 23.3636)
  line L195 (-8.3763, 25.2056) -> (-7.5427, 25.2056)
  line L196 (-7.5427, 25.2056) -> (-7.5427, 23.3636)
  line L197 (-8.3763, 23.3636) -> (-7.5427, 23.3636)
  line L198 (-5.8363, 25.2056) -> (-5.0027, 23.3636) construction
  line L199 (-5.8363, 23.3636) -> (-5.0027, 25.2056) construction
  line L200 (-5.8363, 25.2056) -> (-5.8363, 23.3636)
  line L201 (-5.8363, 25.2056) -> (-5.0027, 25.2056)
  line L202 (-5.0027, 25.2056) -> (-5.0027, 23.3636)
  line L203 (-5.8363, 23.3636) -> (-5.0027, 23.3636)
  line L204 (-3.2963, 25.2056) -> (-2.4627, 23.3636) construction
  line L205 (-3.2963, 23.3636) -> (-2.4627, 25.2056) construction
  line L206 (-3.2963, 25.2056) -> (-3.2963, 23.3636)
  line L207 (-3.2963, 25.2056) -> (-2.4627, 25.2056)
  line L208 (-2.4627, 25.2056) -> (-2.4627, 23.3636)
  line L209 (-3.2963, 23.3636) -> (-2.4627, 23.3636)
  line L210 (-0.7563, 25.2056) -> (0.0773, 23.3636) construction
  line L211 (-0.7563, 23.3636) -> (0.0773, 25.2056) construction
  line L212 (-0.7563, 25.2056) -> (-0.7563, 23.3636)
  line L213 (-0.7563, 25.2056) -> (0.0773, 25.2056)
  line L214 (0.0773, 25.2056) -> (0.0773, 23.3636)
  line L215 (-0.7563, 23.3636) -> (0.0773, 23.3636)
  line L216 (1.7837, 25.2056) -> (2.6173, 23.3636) construction
  line L217 (1.7837, 23.3636) -> (2.6173, 25.2056) construction
  line L218 (1.7837, 25.2056) -> (1.7837, 23.3636)
  line L219 (1.7837, 25.2056) -> (2.6173, 25.2056)
  line L220 (2.6173, 25.2056) -> (2.6173, 23.3636)
  line L221 (1.7837, 23.3636) -> (2.6173, 23.3636)
  line L222 (4.3237, 25.2056) -> (5.1573, 23.3636) construction
  line L223 (4.3237, 23.3636) -> (5.1573, 25.2056) construction
  line L224 (4.3237, 25.2056) -> (4.3237, 23.3636)
  line L225 (4.3237, 25.2056) -> (5.1573, 25.2056)
  line L226 (5.1573, 25.2056) -> (5.1573, 23.3636)
  line L227 (4.3237, 23.3636) -> (5.1573, 23.3636)
  line L228 (10.8677, 25.2056) -> (11.8426, 23.3636) construction
  line L229 (8.3277, 25.2056) -> (9.3026, 25.2056)
  line L230 (8.3277, 25.2056) -> (8.3277, 23.3636)
  line L231 (8.3277, 23.3636) -> (9.3026, 23.3636)
  line L232 (9.3026, 25.2056) -> (9.3026, 23.3636)
  line L233 (8.3277, 25.2056) -> (9.3026, 23.3636) construction
  line L234 (8.3277, 23.3636) -> (9.3026, 25.2056) construction
  line L235 (10.8677, 23.3636) -> (11.8426, 25.2056) construction
  line L236 (10.8677, 25.2056) -> (10.8677, 23.3636)
  line L237 (10.8677, 25.2056) -> (11.8426, 25.2056)
  line L238 (11.8426, 25.2056) -> (11.8426, 23.3636)
  line L239 (10.8677, 23.3636) -> (11.8426, 23.3636)
  line L240 (13.4077, 25.2056) -> (14.3826, 23.3636) construction
  line L241 (13.4077, 23.3636) -> (14.3826, 25.2056) construction
  line L242 (13.4077, 25.2056) -> (13.4077, 23.3636)
  line L243 (13.4077, 25.2056) -> (14.3826, 25.2056)
  line L244 (14.3826, 25.2056) -> (14.3826, 23.3636)
  line L245 (13.4077, 23.3636) -> (14.3826, 23.3636)
  line L246 (15.9477, 25.2056) -> (16.9226, 23.3636) construction
  line L247 (15.9477, 23.3636) -> (16.9226, 25.2056) construction
  line L248 (15.9477, 25.2056) -> (15.9477, 23.3636)
  line L249 (15.9477, 25.2056) -> (16.9226, 25.2056)
  line L250 (16.9226, 25.2056) -> (16.9226, 23.3636)
  line L251 (15.9477, 23.3636) -> (16.9226, 23.3636)
  line L252 (18.4877, 25.2056) -> (19.4626, 23.3636) construction
  line L253 (18.4877, 23.3636) -> (19.4626, 25.2056) construction
  line L254 (18.4877, 25.2056) -> (18.4877, 23.3636)
  line L255 (18.4877, 25.2056) -> (19.4626, 25.2056)
  line L256 (19.4626, 25.2056) -> (19.4626, 23.3636)
  line L257 (18.4877, 23.3636) -> (19.4626, 23.3636)
  line L258 (21.0277, 25.2056) -> (22.0026, 23.3636) construction
  line L259 (21.0277, 23.3636) -> (22.0026, 25.2056) construction
  line L260 (21.0277, 25.2056) -> (21.0277, 23.3636)
  line L261 (21.0277, 25.2056) -> (22.0026, 25.2056)
  line L262 (22.0026, 25.2056) -> (22.0026, 23.3636)
  line L263 (21.0277, 23.3636) -> (22.0026, 23.3636)
  line L264 (23.5677, 25.2056) -> (24.5426, 23.3636) construction
  line L265 (23.5677, 23.3636) -> (24.5426, 25.2056) construction
  line L266 (23.5677, 25.2056) -> (23.5677, 23.3636)
  line L267 (23.5677, 25.2056) -> (24.5426, 25.2056)
  line L268 (24.5426, 25.2056) -> (24.5426, 23.3636)
  line L269 (23.5677, 23.3636) -> (24.5426, 23.3636)
  line L270 (26.1077, 25.2056) -> (27.0826, 23.3636) construction
  line L271 (26.1077, 23.3636) -> (27.0826, 25.2056) construction
  line L272 (26.1077, 25.2056) -> (26.1077, 23.3636)
  line L273 (26.1077, 25.2056) -> (27.0826, 25.2056)
  line L274 (27.0826, 25.2056) -> (27.0826, 23.3636)
  line L275 (26.1077, 23.3636) -> (27.0826, 23.3636)
  line L277 (38.6528, -19.3429) -> (39.3401, -19.3429)
  line L278 (38.6528, -19.3429) -> (38.6528, -16.4789)
  line L279 (38.6528, -16.4789) -> (39.3401, -16.4789)
  line L280 (39.3401, -19.3429) -> (39.3401, -16.4789)
  line L281 (38.6528, -19.3429) -> (39.3401, -16.4789) construction
  line L282 (38.6528, -16.4789) -> (39.3401, -19.3429) construction
  line L283 (45.0872, -19.3429) -> (45.5263, -19.3429)
  line L284 (45.0872, -19.3429) -> (45.0872, -16.4789)
  line L285 (45.0872, -16.4789) -> (45.5263, -16.4789)
  line L286 (45.5263, -19.3429) -> (45.5263, -16.4789)
  line L287 (45.0872, -19.3429) -> (45.5263, -16.4789) construction
  line L288 (45.0872, -16.4789) -> (45.5263, -19.3429) construction
  line L289 (40.7909, -23.3776) -> (43.407, -23.3776)
  line L290 (40.7909, -23.3776) -> (40.7909, -22.6651)
  line L291 (40.7909, -22.6651) -> (43.407, -22.6651)
  line L292 (43.407, -23.3776) -> (43.407, -22.6651)
  line L293 (40.7909, -23.3776) -> (43.407, -22.6651) construction
  line L294 (40.7909, -22.6651) -> (43.407, -23.3776) construction
  line L295 (46.2946, 17.9846) -> (48.551, 17.9846)
  line L296 (46.2946, 17.9846) -> (46.2946, 17.1072)
  line L297 (46.2946, 17.1072) -> (48.551, 17.1072)
  line L298 (48.551, 17.9846) -> (48.551, 17.1072)
  line L299 (46.2946, 17.9846) -> (48.551, 17.1072) construction
  line L300 (46.2946, 17.1072) -> (48.551, 17.9846) construction
  line L301 (46.5224, 5.8456) -> (48.3233, 5.8456)
  line L302 (46.5224, 5.8456) -> (46.5224, 4.9898)
  line L303 (46.5224, 4.9898) -> (48.3233, 4.9898)
  line L304 (48.3233, 5.8456) -> (48.3233, 4.9898)
  line L305 (46.5224, 5.8456) -> (48.3233, 4.9898) construction
  line L306 (46.5224, 4.9898) -> (48.3233, 5.8456) construction
  circle A0 centre (-46.7648, -19.4233) radius 0.5739
  circle A1 centre (-44.2248, -19.4233) radius 0.5739
  circle A2 centre (-46.7648, -16.8833) radius 0.5739
  circle A3 centre (-44.2248, -16.8833) radius 0.5739
  circle A4 centre (-46.7648, -14.3433) radius 0.5739
  circle A5 centre (-44.2248, -14.3433) radius 0.5739
  circle A6 centre (-46.7648, -11.8033) radius 0.5739
  circle A7 centre (-44.2248, -11.8033) radius 0.5739
  circle A8 centre (-46.7648, -9.2633) radius 0.5739
  circle A9 centre (-44.2248, -9.2633) radius 0.5739
  circle A10 centre (-46.7648, -6.7233) radius 0.5739
  circle A11 centre (-44.2248, -6.7233) radius 0.5739
  circle A12 centre (-46.7648, -4.1833) radius 0.5739
  circle A13 centre (-44.2248, -4.1833) radius 0.5739
  circle A14 centre (-46.7648, -1.6433) radius 0.5739
  circle A15 centre (-44.2248, -1.6433) radius 0.5739
  circle A16 centre (-46.7648, 0.8967) radius 0.5739
  circle A17 centre (-44.2248, 0.8967) radius 0.5739
  circle A18 centre (-46.7648, 3.4367) radius 0.5739
  circle A19 centre (-44.2248, 3.4367) radius 0.5739
  circle A20 centre (-46.7648, 5.9767) radius 0.5739
  circle A21 centre (-44.2248, 5.9767) radius 0.5739
  circle A22 centre (-46.7648, 8.5167) radius 0.5739
  circle A23 centre (-44.2248, 8.5167) radius 0.5739
  circle A24 centre (-46.7648, 11.0567) radius 0.5739
  circle A25 centre (-44.2248, 11.0567) radius 0.5739
  circle A26 centre (-46.7648, 13.5967) radius 0.5739
  circle A27 centre (-44.2248, 13.5967) radius 0.5739
  circle A28 centre (-46.7648, 16.1367) radius 0.5739
  circle A29 centre (-44.2248, 16.1367) radius 0.5739
  circle A30 centre (-46.7648, 18.6767) radius 0.5739
  circle A31 centre (-44.2248, 18.6767) radius 0.5739
  circle A32 centre (-46.7648, 21.2167) radius 0.5739
  circle A33 centre (-44.2248, 21.2167) radius 0.5739
  circle A34 centre (-46.7648, 23.7567) radius 0.5739
  circle A35 centre (-44.2248, 23.7567) radius 0.5739
  circle A36 centre (30.2055, 20.9703) radius 0.5437
  circle A37 centre (32.7455, 20.9703) radius 0.5437
  circle A38 centre (35.2855, 20.9703) radius 0.5437
  circle A39 centre (30.2055, 18.4303) radius 0.5437
  circle A40 centre (32.7455, 18.4303) radius 0.5437
  circle A41 centre (35.2855, 18.4303) radius 0.5437
  circle A42 centre (42.5134, 12.8688) radius 0.4144
  circle A43 centre (45.0534, 12.8688) radius 0.4144
  circle A44 centre (42.5134, 10.3288) radius 0.4144
  circle A45 centre (45.0534, 10.3288) radius 0.4144
  point P0 (-41.5058, -24.5263)
  point P5 (-18.4034, -24.3202)
  point P6 (-38.9658, -24.5263)
  point P11 (-36.4258, -24.5263)
  point P16 (-33.8858, -24.5263)
  point P21 (-31.3458, -24.5263)
  point P26 (-28.8058, -24.5263)
  point P31 (-26.2658, -24.5263)
  point P36 (-23.7258, -24.5263)
  point P45 (4.7745, -24.0588)
  point P46 (-15.8634, -24.3202)
  point P51 (-13.3234, -24.3202)
  point P56 (-10.7834, -24.3202)
  point P61 (-8.2434, -24.3202)
  point P66 (-5.7034, -24.3202)
  point P71 (-3.1634, -24.3202)
  point P76 (-0.6234, -24.3202)
  point P86 (7.3145, -24.0588)
  point P91 (9.8545, -24.0588)
  point P96 (12.3945, -24.0588)
  point P101 (14.9345, -24.0588)
  point P106 (17.4745, -24.0588)
  point P112 (-36.4258, 24.1617)
  point P187 (-13.0395, 24.2846)
  point P188 (-33.8858, 24.1617)
  point P193 (-31.3458, 24.1617)
  point P198 (-28.8058, 24.1617)
  point P203 (-26.2658, 24.1617)
  point P208 (-23.7258, 24.1617)
  point P213 (-21.1858, 24.1617)
  point P218 (-18.6458, 24.1617)
  point P227 (8.8152, 24.2846)
  point P228 (-10.4995, 24.2846)
  point P233 (-7.9595, 24.2846)
  point P238 (-5.4195, 24.2846)
  point P243 (-2.8795, 24.2846)
  point P248 (-0.3395, 24.2846)
  point P253 (2.2005, 24.2846)
  point P258 (4.7405, 24.2846)
  point P268 (11.3552, 24.2846)
  point P273 (13.8952, 24.2846)
  point P278 (16.4352, 24.2846)
  point P283 (18.9752, 24.2846)
  point P288 (21.5152, 24.2846)
  point P293 (24.0552, 24.2846)
  point P298 (26.5952, 24.2846)
  point P316 (38.9965, -17.9109)
  point P327 (45.3068, -17.9109)
  point P332 (42.0989, -23.0214)
  point P337 (47.4228, 17.5459)
  point P342 (47.4228, 5.4177)
  dimension "D1" = 18
  dimension "D2" = 2
  dimension "D3" = 2
extrude "Boss-Extrude17" add sketch "Sketch25" along normal blind 0.508 draft 48
fillet "Fillet4" radius 0.0635 66 edges at (-12.7627, -1.9631, -2.54) (-12.2164, -1.1228, -2.54) (-16.0647, -1.9631, -2.54) (-15.7472, -1.6456, -2.54) (-15.4297, 0.8309, -2.54) (-15.7472, 0.5134, -2.54) (-12.2164, -0.0094, -2.54) (-11.7084, 0.8309, -2.54) (-13.0802, 1.1484, -2.54) (-13.0802, 0.5134, -2.54) (-15.4297, 3.6249, -2.54) (-12.2164, 4.4652, -2.54) (-14.4137, 4.9732, -2.54) (34.9076, 20.6953, -2.54) (34.3869, 21.5589, -2.54) (35.2251, 18.3458, -2.54) (31.0849, 19.3618, -2.54) (33.2693, 17.1647, -2.54) (33.7773, 19.3618, -2.54) (29.3196, 18.0283, -2.54) (29.9546, 18.0283, -2.54) (29.6371, 22.0669, -2.54) (28.7989, 17.1647, -2.54) (29.6371, 16.6567, -2.54) (30.4753, 17.1647, -2.54) (29.1555, -23.0456, -1.397) (31.173, -24.269, -1.397) (11.332, -19.8889, -1.397) (9.7086, -12.346, -1.397) (11.73, -12.3915, -1.397) (15.1651, -10.7617, -1.397) (14.2392, -12.3915, -1.397) (15.1651, -14.0213, -1.397) (16.091, -12.3915, -1.397) (22.8851, -8.3755, -1.397) (28.5657, 2.3794, -1.397) (32.3844, 2.8127, -1.397) (32.3287, -12.1294, -1.397) (32.3896, -7.1173, -1.397) (33.7999, -5.6867, -1.397) (35.6205, 2.6802, -1.397) (34.854, 2.3132, -1.397) (38.0454, 7.3895, -1.397) (39.3497, 10.1498, -1.397) (38.8465, 12.4687, -1.397) (38.8465, 4.309, -1.397) (38.0454, 3.9713, -1.397) (38.0454, 2.3132, -1.397) (38.7803, 1.9462, -1.397) (42.3058, -12.5341, -1.397) (43.9403, -9.2877, -1.397) (48.1172, -0.3139, -1.397) (38.8465, 15.6816, -1.397) (41.7321, 18.2863, -1.397) (38.0675, 20.9935, -1.397) (37.1574, 19.3676, -1.397) (38.0675, 17.7416, -1.397) (38.9776, 19.3676, -1.397) (25.3776, 2.3794, -1.397) (26.1593, 1.9462, -1.397) (23.5707, -5.4505, -1.397) (22.9484, -1.1659, -1.397) (22.9964, 6.7341, -1.397) (22.5161, 12.4687, -1.397) (-0.0563, 8.5631, -1.397) (-7.073, 1.4641, -1.397)
fillet "Fillet5" radius 0.0635 15 edges at (38.4048, -22.1361, -3.2385) (38.4048, -14.5161, -3.2385) (52.6288, -15.1511, -6.35) (40.5638, -15.1511, -6.35) (40.005, -14.5161, -3.2385) (40.005, -13.7541, -3.2385) (40.005, -22.1361, -3.2385) (40.005, -22.8981, -3.2385) (38.4048, -18.3261, -10.287) (44.5389, -14.5161, -6.477) (44.5389, -22.1361, -6.477) (50.8508, -13.7541, -10.795) (50.8508, -22.8981, -10.795)
